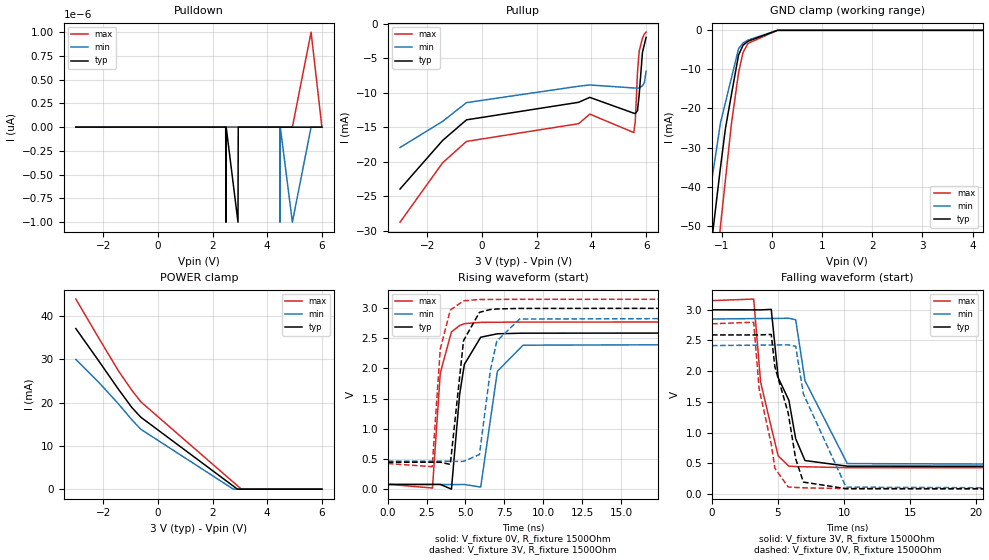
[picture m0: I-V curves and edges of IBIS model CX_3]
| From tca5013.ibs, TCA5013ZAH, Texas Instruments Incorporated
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[Model]   CX_3
Model_type   I/O
Polarity   Non-Inverting
Enable   Active-Low
Vinl = 1.2
Vinh = 1.8
Vmeas = 1.5
Vref = 3
Cref = 1pF
Rref = 1500
|   typ   min   max
C_comp   0.819p   0.538p   1.031p
|C_comp (ON state)   0.835p   0.552p   1.076p
|C_comp (OFF state)   0.819p   0.538p   1.031p
[Model spec]
|subparameter
Vinl   1.2   1.14   1.26
Vinh   1.8   1.71   1.89
[Voltage Range]   3   2.85   3.15
[Temperature Range]   27   125   -40
[Pullup Reference]   3   2.85   3.15
[Pulldown Reference]   0   0   0
[Power Clamp Reference]   3   2.85   3.15
[GND Clamp Reference]   0   0   0
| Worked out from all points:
|   GND clamp passes 1 mA (typ) near -0.12 V on its own axis
|   falling waveform, V_fixture 3V, R_fixture 1500Ohm: 20-80 % time 1.53ns typ, 2.05ns min, 1.2ns max; typ from 3 V to 0.448 V
|   rising waveform, V_fixture 0V, R_fixture 1500Ohm: 20-80 % time 634ps typ, 780ps min, 536ps max; typ from 0.08 V to 2.59 V
|   rising waveform, V_fixture 3V, R_fixture 1500Ohm: 20-80 % time 622ps typ, 770ps min, 532ps max; typ from 0.448 V to 3 V
|   falling waveform, V_fixture 0V, R_fixture 1500Ohm: 20-80 % time 1.57ns typ, 2.1ns min, 1.24ns max; typ from 2.59 V to 0.08 V
[Pulldown]
|   Voltage   I(typ)   I(min)   I(max)
-3V       0A         0A         0A
2.481V    0A         0A         0A
2.49V     -1pA       0A         0A
2.499V    0A         0A         0A
2.931V    -1pA       0A         0A
2.94V     0A         0A         0A
4.461V    0A         0A         0A
4.47V     0A         -1pA       0A
4.479V    0A         0A         0A
4.92V     0A         -1pA       0A
5.604V    0A         0A         1pA
6V        0A         0A         0A
[GND Clamp]
|   Voltage   I(typ)   I(min)   I(max)
-3V       -434mA     -224.4mA   -707.7mA
-1.38V    -74.24mA   -53.32mA   -98.3mA
-1.29V    -63.61mA   -45.71mA   -85.56mA
-1.182V   -51.54mA   -36.57mA   -70.32mA
-1.029V   -34.96mA   -23.63mA   -49.98mA
-930mV    -25.05mA   -18.42mA   -38.12mA
-813.2mV  -16.55mA   -12.27mA   -24.13mA
-669mV    -6.316mA   -4.694mA   -10.85mA
-579mV    -3.803mA   -3.238mA   -5.623mA
-480mV    -2.788mA   -2.484mA   -3.335mA
105mV     0A         0A         0A
6V        0A         0A         0A
[Pullup]
|   Voltage   I(typ)   I(min)   I(max)
-3V       -23.92mA   -17.92mA   -28.72mA
-1.443V   -16.9mA    -14.14mA   -20.13mA
-570mV    -13.92mA   -11.43mA   -17.04mA
3.534V    -11.38mA   -9.054mA   -14.47mA
3.939V    -10.67mA   -8.875mA   -13.09mA
5.55V     -12.96mA   -9.31mA    -15.76mA
5.604V    -13.01mA   -9.314mA   -14.11mA
5.685V    -12.58mA   -9.318mA   -7.007mA
5.748V    -10.22mA   -9.315mA   -3.964mA
5.866V    -4.161mA   -8.988mA   -2.102mA
5.937V    -3.011mA   -8.538mA   -1.501mA
6V        -1.993mA   -6.882mA   -1.228mA
[POWER Clamp]
|   Voltage   I(typ)   I(min)   I(max)
-3V       37.13mA    30.01mA    43.95mA
-2.172V   29.74mA    24.78mA    35.05mA
-1.443V   23.11mA    19.73mA    27.35mA
-948mV    18.85mA    16.03mA    22.83mA
-624mV    16.64mA    13.85mA    20.2mA
2.751V    749.9uA    37.34uA    1.659mA
2.904V    21.74uA    0A         826.6uA
3.048V    0A         0A         43.64uA
6V        0A         0A         0A
[Ramp]
R_load = 1500
|   typ   min   max
dV/dt_r   1.50633/6.33602e-10   1.40333/7.81109e-10   1.61297/5.3699e-10
dV/dt_f   1.53142/1.52711e-09   1.43045/2.04544e-09   1.63426/1.19826e-09
[Falling Waveform]
V_fixture = 3V
V_fixture_min = 2.85V
V_fixture_max = 3.15V
R_fixture = 1500Ohm
C_fixture = 0F
|   Time   V(typ)   V(min)   V(max)
0s        3V         2.85V      3.15V
3.163ns   2.999V     2.857V     3.175V
3.685ns   2.999V     2.858V     1.823V
4.491ns   3.007V     2.859V     1.087V
5.017ns   1.893V     2.86V      619.5mV
5.827ns   1.526V     2.862V     452.3mV
6.341ns   900.1mV    2.837V     446.7mV
7.046ns   544.4mV    1.845V     442.7mV
10.25ns   452.7mV    494.7mV    428.2mV
49.9ns    447.6mV    465.9mV    426.2mV
[Rising Waveform]
V_fixture = 0V
V_fixture_min = 0V
V_fixture_max = 0V
R_fixture = 1500Ohm
C_fixture = 0F
|   Time   V(typ)   V(min)   V(max)
0s        80.25mV    77.98mV    83.74mV
2.877ns   80.48mV    78.21mV    19.89mV
3.379ns   80.52mV    78.25mV    1.925V
4.097ns   1.257mV    78.3mV     2.606V
4.624ns   1.571V     78.34mV    2.712V
4.928ns   2.068V     78.37mV    2.743V
5.979ns   2.518V     35.79mV    2.764V
7.052ns   2.575V     1.955V     2.766V
8.704ns   2.585V     2.386V     2.769V
49.9ns    2.591V     2.417V     2.772V
[Rising Waveform]
V_fixture = 3V
V_fixture_min = 2.85V
V_fixture_max = 3.15V
R_fixture = 1500Ohm
C_fixture = 0F
|   Time   V(typ)   V(min)   V(max)
0s        447.6mV    465.8mV    426.1mV
2.859ns   447.7mV    463.4mV    373.8mV
3.379ns   447.7mV    463mV      2.323V
4.024ns   411.3mV    462.5mV    2.968V
4.874ns   2.461V     461.8mV    3.121V
5.898ns   2.93V      573.9mV    3.143V
6.595ns   2.977V     1.962V     3.144V
7.016ns   2.986V     2.455V     3.144V
8.48ns    2.995V     2.819V     3.146V
49.9ns    3V         2.85V      3.15V
[Falling Waveform]
|Gnd
V_fixture = 0V
V_fixture_min = 0V
V_fixture_max = 0V
R_fixture = 1500Ohm
C_fixture = 0F
|   Time   V(typ)   V(min)   V(max)
0s        2.591V     2.417V     2.772V
3.163ns   2.59V      2.424V     2.798V
3.569ns   2.59V      2.425V     1.719V
4.491ns   2.599V     2.427V     812mV
4.765ns   2.072V     2.427V     418.5mV
5.774ns   1.319V     2.429V     113.3mV
6.341ns   571.8mV    2.405V     105.7mV
6.926ns   193.1mV    1.628V     100.2mV
10.16ns   86.45mV    110mV      86.5mV
49.9ns    80.25mV    77.98mV    83.74mV
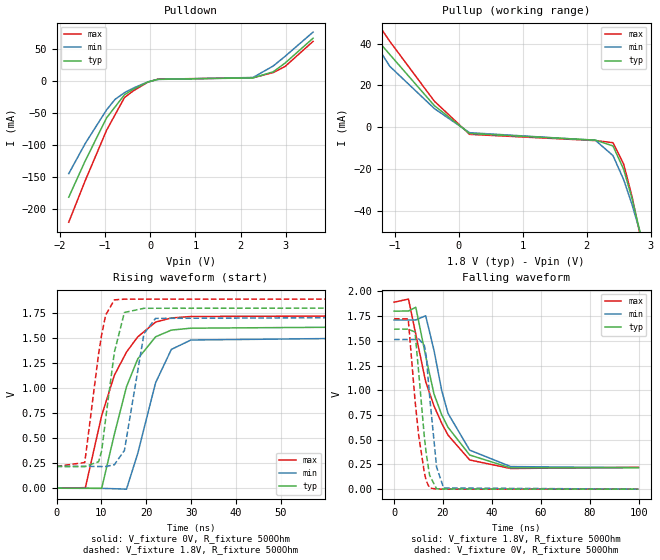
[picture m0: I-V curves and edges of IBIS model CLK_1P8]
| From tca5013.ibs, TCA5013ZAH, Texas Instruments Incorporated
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|   Model CLK
[Model]   CLK_1P8
Model_type   Output
Polarity   Non-Inverting
Vmeas = 0.9
Vref = 1.8
Cref = 1pF
Rref = 500
|   typ   min   max
C_comp   0.597p   0.445p   0.907p
|C_comp (ON state)   0.597p   0.445p   0.907p
|C_comp (OFF state)   0.592p   0.445p   0.907p
[Voltage Range]   1.8   1.71   1.89
[Temperature Range]   27   125   -40
[Pullup Reference]   1.8   1.71   1.89
[Pulldown Reference]   0   0   0
[Power Clamp Reference]   1.8   1.71   1.89
[GND Clamp Reference]   0   0   0
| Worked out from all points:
|   slope of the pulldown table from 0 to 0.27 V, typ, clamps not added: 80.3 ohm
|   slope of the pullup table from 0 to 0.27 V, typ, clamps not added: 64.9 ohm
|   falling waveform, V_fixture 1.8V, R_fixture 500Ohm: 20-80 % time 12.4ns typ, 10.7ns min, 12.9ns max; typ from 1.8 V to 0.218 V
|   rising waveform, V_fixture 0V, R_fixture 500Ohm: 20-80 % time 6.22ns typ, 5.54ns min, 7.57ns max; typ from 0 V to 1.62 V
|   rising waveform, V_fixture 1.8V, R_fixture 500Ohm: 20-80 % time 2.79ns typ, 2.97ns min, 2.98ns max; typ from 0.218 V to 1.8 V
|   falling waveform, V_fixture 0V, R_fixture 500Ohm: 20-80 % time 3.62ns typ, 3.34ns min, 4.13ns max; typ from 1.62 V to 0 V
[Pulldown]
|   Voltage   I(typ)   I(min)   I(max)
-1.8V     -181.5mA   -144.7mA   -220.6mA
-1.438V   -125mA     -97.81mA   -156mA
-963mV    -57.33mA   -44.83mA   -76.73mA
-774mV    -40.13mA   -28.44mA   -52.34mA
-567.1mV  -21.31mA   -18.07mA   -25.64mA
-379.8mV  -12.97mA   -11.16mA   -15.54mA
-50.4mV   -1.481mA   -1.108mA   -1.576mA
171mV     2.826mA    2.586mA    3.048mA
2.272V    4.956mA    5.651mA    5.216mA
2.72V     14.57mA    23.66mA    13.38mA
2.979V    28.07mA    38.59mA    22.75mA
3.6V      67.05mA    76.62mA    62.13mA
[Pullup]
|   Voltage   I(typ)   I(min)   I(max)
-1.8V     65mA       67.66mA    73.64mA
-1.438V   47.62mA    46.48mA    57.36mA
-1.075V   34.73mA    29.08mA    41.03mA
-379.8mV  10.31mA    8.9mA      12.43mA
171mV     -3.048mA   -2.661mA   -3.448mA
2.137V    -6.212mA   -6.303mA   -6.432mA
2.412V    -9.003mA   -13.62mA   -7.448mA
2.579V    -20.22mA   -25.14mA   -17.73mA
2.709V    -34.17mA   -37.01mA   -33.2mA
2.866V    -54.2mA    -53.43mA   -56.12mA
3.06V     -81.74mA   -75.9mA    -87.8mA
3.6V      -165.3mA   -145.3mA   -183mA
[Ramp]
R_load = 500
|   typ   min   max
dV/dt_r   0.972083/6.21813e-09   0.908449/5.5359e-09   1.03477/7.56584e-09
dV/dt_f   0.949299/1.23787e-08   0.895838/1.06834e-08   1.00117/1.29267e-08
[Falling Waveform]
V_fixture = 1.8V
V_fixture_min = 1.71V
V_fixture_max = 1.89V
R_fixture = 500Ohm
C_fixture = 0F
|   Time   V(typ)   V(min)   V(max)
0s        1.8V       1.71V      1.89V
5.898ns   1.801V     1.711V     1.922V
8.884ns   1.839V     1.711V     1.566V
12.93ns   1.345V     1.753V     1.086V
16.32ns   963.2mV    1.404V     841.6mV
19.49ns   750.9mV    997.5mV    665.9mV
22.05ns   626.1mV    766.7mV    547.1mV
30.92ns   345.3mV    394.8mV    295.2mV
47.71ns   214.8mV    228.4mV    208.9mV
99.9ns    217.8mV    216.9mV    221.4mV
[Rising Waveform]
V_fixture = 0V
V_fixture_min = 0V
V_fixture_max = 0V
R_fixture = 500Ohm
C_fixture = 0F
|   Time   V(typ)   V(min)   V(max)
0s        72.81nV    528.5nV    56.66nV
6.428ns   -1.095mV   40.67uV    5.639mV
10.06ns   -846.4uV   -1.522mV   726.4mV
12.88ns   538.1mV    -5.119mV   1.128V
15.59ns   1.014V     -9.441mV   1.361V
18.09ns   1.292V     347.5mV    1.512V
22.07ns   1.513V     1.054V     1.66V
25.58ns   1.58V      1.387V     1.701V
29.94ns   1.599V     1.481V     1.716V
99.9ns    1.62V      1.514V     1.725V
[Rising Waveform]
V_fixture = 1.8V
V_fixture_min = 1.71V
V_fixture_max = 1.89V
R_fixture = 500Ohm
C_fixture = 0F
|   Time   V(typ)   V(min)   V(max)
0s        217.5mV    218.2mV    217.9mV
6.289ns   216.4mV    218.3mV    256.9mV
9.385ns   265mV      217.1mV    1.348V
10.06ns   374mV      216.3mV    1.534V
10.95ns   695.6mV    217.3mV    1.73V
12.88ns   1.358V     234.6mV    1.882V
15.12ns   1.756V     376.8mV    1.889V
19.49ns   1.798V     1.545V     1.889V
22.05ns   1.798V     1.697V     1.889V
99.9ns    1.8V       1.71V      1.89V
[Falling Waveform]
|Gnd
V_fixture = 0V
V_fixture_min = 0V
V_fixture_max = 0V
R_fixture = 500Ohm
C_fixture = 0F
|   Time   V(typ)   V(min)   V(max)
0s        1.618V     1.513V     1.723V
5.787ns   1.618V     1.513V     1.722V
8.573ns   1.589V     1.513V     896.8mV
10.08ns   1.18V      1.52V      541.8mV
12.4ns    523.8mV    1.452V     164.9mV
13.19ns   355.5mV    1.335V     81.77mV
14.54ns   139.8mV    940.3mV    12.54mV
17.39ns   3.621mV    223.5mV    560uV
20.25ns   1.613mV    12.29mV    843.7uV
99.9ns    102.4uV    166.3uV    64.26uV
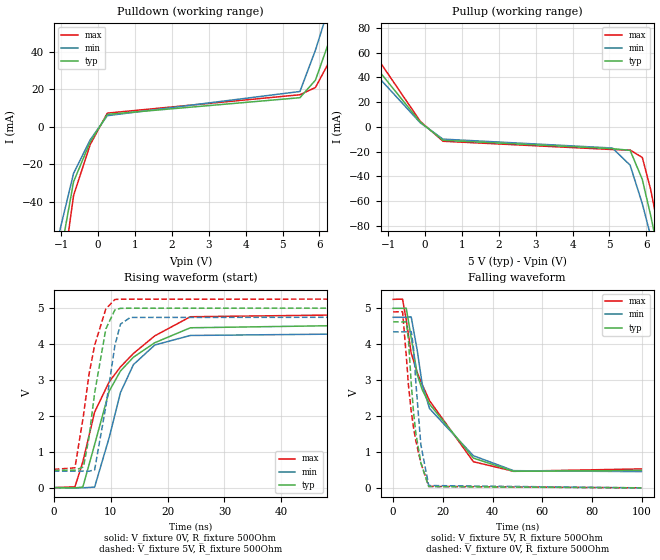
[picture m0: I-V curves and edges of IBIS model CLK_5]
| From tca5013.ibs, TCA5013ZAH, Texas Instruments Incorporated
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[Model]   CLK_5
Model_type   Output
Polarity   Non-Inverting
Vmeas = 2.5
Vref = 5
Cref = 1pF
Rref = 500
|   typ   min   max
C_comp   0.937p   0.723p   1.081p
|C_comp (ON state)   0.950p   0.730p   1.090p
|C_comp (OFF state)   0.937p   0.723p   1.081p
[Voltage Range]   5   4.75   5.25
[Temperature Range]   27   125   -40
[Pullup Reference]   5   4.75   5.25
[Pulldown Reference]   0   0   0
[Power Clamp Reference]   5   4.75   5.25
[GND Clamp Reference]   0   0   0
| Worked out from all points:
|   slope of the pulldown table from 0 to 0.75 V, typ, clamps not added: 77.3 ohm
|   slope of the pullup table from 0 to 0.75 V, typ, clamps not added: 60.3 ohm
|   falling waveform, V_fixture 5V, R_fixture 500Ohm: 20-80 % time 16.5ns typ, 15.2ns min, 16.2ns max; typ from 5 V to 0.485 V
|   rising waveform, V_fixture 0V, R_fixture 500Ohm: 20-80 % time 7.69ns typ, 5.2ns min, 9.94ns max; typ from 0 V to 4.63 V
|   rising waveform, V_fixture 5V, R_fixture 500Ohm: 20-80 % time 2.5ns typ, 2.42ns min, 2.91ns max; typ from 0.486 V to 5 V
|   falling waveform, V_fixture 0V, R_fixture 500Ohm: 20-80 % time 3.91ns typ, 3.1ns min, 5.07ns max; typ from 4.62 V to 0 V
[Pulldown]
|   Voltage   I(typ)   I(min)   I(max)
-5V       -2.371A    -1.943A    -2.674A
-2.495V   -297.4mA   -245.6mA   -349.6mA
-1.25V    -100.1mA   -78.8mA    -127.6mA
-1.04V    -70.39mA   -55.45mA   -90.18mA
-665mV    -29.23mA   -24.77mA   -36.56mA
-215mV    -8.057mA   -6.927mA   -9.442mA
250mV     6.693mA    6.01mA     7.374mA
5.47V     15.6mA     18.91mA    17.18mA
5.89V     24.96mA    40.96mA    21.05mA
6.28V     46.74mA    65.38mA    35.36mA
7.675V    147.7mA    163.9mA    140.1mA
10V       342.3mA    375.7mA    355.4mA
[Pullup]
|   Voltage   I(typ)   I(min)   I(max)
-5V       273.3mA    294.8mA    295.7mA
-2.3V     96.77mA    99.19mA    104.5mA
-1.25V    45.3mA     39.76mA    53.7mA
-125mV    3.799mA    3.278mA    4.46mA
490mV     -10.77mA   -9.84mA    -11.56mA
5.08V     -17.53mA   -17.02mA   -18.24mA
5.56V     -18.91mA   -30.91mA   -18.7mA
5.89V     -42.38mA   -61.97mA   -24.65mA
6.115V    -71.26mA   -87.96mA   -50.3mA
6.25V     -90.54mA   -104.6mA   -70.56mA
7.735V    -327.5mA   -309.1mA   -334.5mA
10V       -2.371A    -2.188A    -2.426A
[Ramp]
R_load = 500
|   typ   min   max
dV/dt_r   2.7772/7.68381e-09   2.61104/5.20304e-09   2.94322/9.89574e-09
dV/dt_f   2.70922/1.65153e-08   2.57881/1.52113e-08   2.83329/1.62101e-08
[Falling Waveform]
V_fixture = 5V
V_fixture_min = 4.75V
V_fixture_max = 5.25V
R_fixture = 500Ohm
C_fixture = 0F
|   Time   V(typ)   V(min)   V(max)
0s        5V         4.75V      5.25V
3.789ns   5V         4.75V      5.256V
5.269ns   5.005V     4.75V      4.681V
7.273ns   4.195V     4.762V     3.753V
9.731ns   3.145V     3.818V     3.21V
11.72ns   2.732V     2.881V     2.873V
14.68ns   2.329V     2.207V     2.425V
32.3ns    829.2mV    895.1mV    728.3mV
48.5ns    461.1mV    478.7mV    461.3mV
99.9ns    484.6mV    452mV      527.9mV
[Rising Waveform]
V_fixture = 0V
V_fixture_min = 0V
V_fixture_max = 0V
R_fixture = 500Ohm
C_fixture = 0F
|   Time   V(typ)   V(min)   V(max)
0s        112.9nV    473.4nV    94.34nV
3.714ns   -6.194mV   -4.421mV   23.1mV
5.099ns   14.87mV    -6.07mV    717.7mV
7.175ns   1.2V       15.94mV    2.104V
9.731ns   2.687V     1.391V     2.946V
11.72ns   3.248V     2.648V     3.362V
14ns      3.633V     3.426V     3.737V
17.75ns   4.036V     3.972V     4.227V
24.01ns   4.452V     4.238V     4.759V
99.9ns    4.629V     4.352V     4.905V
[Rising Waveform]
V_fixture = 5V
V_fixture_min = 4.75V
V_fixture_max = 5.25V
R_fixture = 500Ohm
C_fixture = 0F
|   Time   V(typ)   V(min)   V(max)
0s        486mV      461mV      509.1mV
3.714ns   486.2mV    461.2mV    551.4mV
5.207ns   574.4mV    461.3mV    2.006V
6.174ns   1.388V     456.8mV    3.142V
7.175ns   2.631V     496.9mV    3.965V
9.149ns   4.42V      2.262V     4.98V
10.74ns   4.95V      3.959V     5.24V
11.72ns   4.994V     4.553V     5.249V
13.45ns   4.997V     4.74V      5.249V
99.9ns    5V         4.75V      5.25V
[Falling Waveform]
|Gnd
V_fixture = 0V
V_fixture_min = 0V
V_fixture_max = 0V
R_fixture = 500Ohm
C_fixture = 0F
|   Time   V(typ)   V(min)   V(max)
0s        4.622V     4.345V     4.899V
3.81ns    4.622V     4.345V     4.907V
5.306ns   4.621V     4.345V     3.667V
6.174ns   4.12V      4.345V     2.859V
7.311ns   2.891V     4.353V     2.118V
8.241ns   2.092V     3.874V     1.668V
9.149ns   1.522V     2.937V     1.31V
11.16ns   693.5mV    1.203V     697.9mV
14.34ns   35.44mV    64.72mV    40.68mV
99.9ns    33.66uV    72.92uV    10.41uV
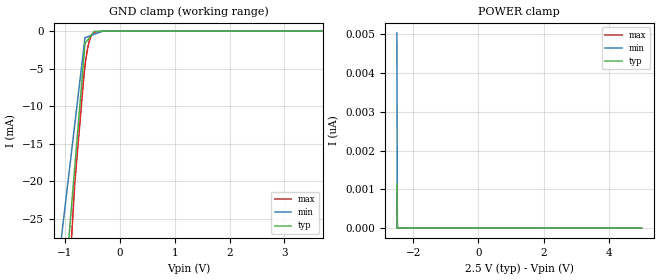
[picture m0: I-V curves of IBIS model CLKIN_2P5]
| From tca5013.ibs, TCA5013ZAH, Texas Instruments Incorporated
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[Model]   CLKIN_2P5
Model_type   Input
Vinl = .5
Vinh = 2.0
|   typ   min   max
C_comp   0.731p   0.503p   0.930p
[Model spec]
|subparameter
Vinl   0.5   0.45   0.55
Vinh   2.0   1.8   2.2
[Voltage Range]   2.5   2.25   2.75
[Temperature Range]   27   125   -40
[Power Clamp Reference]   2.5   2.25   2.75
[GND Clamp Reference]   0   0   0
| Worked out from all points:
|   GND clamp passes 1 mA (typ) near -0.57 V on its own axis
[GND Clamp]
|   Voltage   I(typ)   I(min)   I(max)
-2.5V     -203.5mA   -158.5mA   -265.9mA
-1.383V   -68.06mA   -47.4mA    -91.06mA
-820mV    -18.25mA   -12.51mA   -20.38mA
-647.5mV  -2.977mA   -1.809mA   -5.543mA
-632.5mV  -1.649mA   -878.3uA   -4.63mA
-610mV    -1.431mA   -817.7uA   -3.421mA
-587.5mV  -1.212mA   -757.1uA   -2.416mA
-557.5mV  -921.6uA   -676.2uA   -1.405mA
-520mV    -557.9uA   -575.1uA   -626.6uA
-467.5mV  -48.79uA   -433.7uA   -163.3uA
-307mV    -424.6nA   -1.005uA   -651.4nA
5V        0A         0A         0A
[POWER Clamp]
|   Voltage   I(typ)   I(min)   I(max)
-2.5V     1.151nA    5.033nA    768pA
-2.485V   0A         0A         0A
-512.5mV  0A         0A         0A
5V        0A         0A         0A
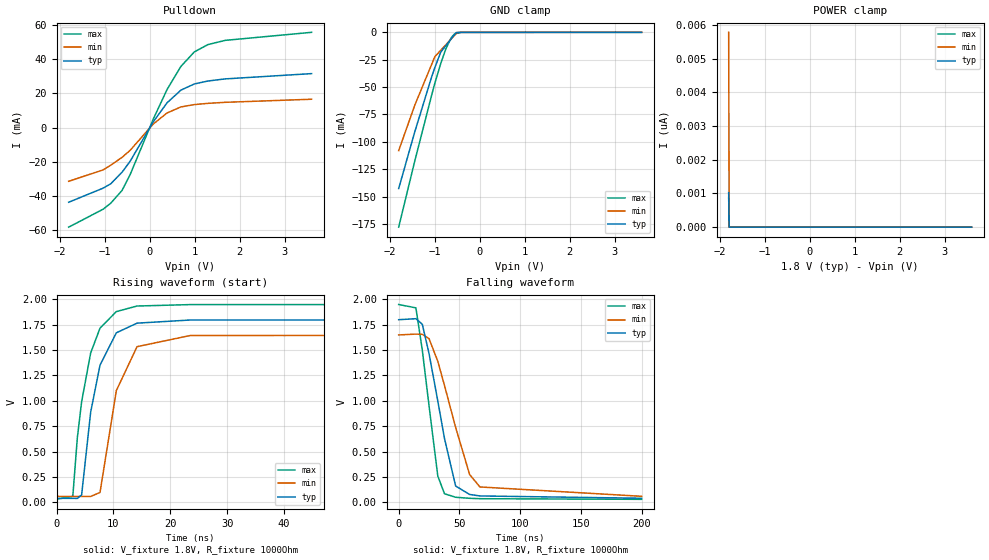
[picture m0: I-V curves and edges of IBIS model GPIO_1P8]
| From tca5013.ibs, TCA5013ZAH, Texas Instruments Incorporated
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|   Model GPIO
[Model]   GPIO_1P8
Model_type   I/O_open_drain
Polarity   Non-Inverting
Enable   Active-Low
Vinl = .4
Vinh = 1.4
Vmeas = 0.9
Vref = 1.8
Cref = 15pF
Rref = 1000
|   typ   min   max
C_comp   0.924p   0.657p   1.281p
|C_comp (Low state)   1.051p   0.694p   1.583p
|C_comp (High state)   0.924p   0.657p   1.281p
[Voltage Range]   1.8   1.65   1.95
[Temperature Range]   27   125   -40
[Pullup Reference]   1.8   1.65   1.95
[Pulldown Reference]   0   0   0
[Power Clamp Reference]   1.8   1.65   1.95
[GND Clamp Reference]   0   0   0
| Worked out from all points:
|   slope of the pulldown table from 0 to 0.27 V, typ, clamps not added: 25.3 ohm
|   GND clamp passes 1 mA (typ) near -0.54 V on its own axis
|   falling waveform, V_fixture 1.8V, R_fixture 1000Ohm: 20-80 % time 16ns typ, 21.8ns min, 11.7ns max; typ from 1.8 V to 0.039 V
|   rising waveform, V_fixture 1.8V, R_fixture 1000Ohm: 20-80 % time 3.18ns typ, 3.28ns min, 3.15ns max; typ from 0.039 V to 1.8 V
[Pulldown]
|   Voltage   I(typ)   I(min)   I(max)
-1.8V     -43.54mA   -31.32mA   -58.1mA
-1.035V   -35.32mA   -24.65mA   -47.62mA
-865.8mV  -32.8mA    -21.91mA   -44.14mA
-612mV    -25.96mA   -17.3mA    -36.59mA
-433.8mV  -19.6mA    -13.22mA   -27.4mA
79.2mV    3.391mA    2.126mA    4.96mA
387mV     14.54mA    8.61mA     22.29mA
694.8mV   21.94mA    12.13mA    35.81mA
991.8mV   25.54mA    13.5mA     44.26mA
1.294V    27.27mA    14.23mA    48.54mA
1.678V    28.51mA    14.83mA    51.02mA
3.6V      31.6mA     16.63mA    55.72mA
[GND Clamp]
|   Voltage   I(typ)   I(min)   I(max)
-1.8V     -142.7mA   -108.1mA   -178mA
-1.438V   -90.37mA   -66.14mA   -116.9mA
-1.065V   -40.44mA   -29.09mA   -57.11mA
-995.4mV  -32.15mA   -22.18mA   -46.43mA
-865.8mV  -18.17mA   -16.42mA   -28.63mA
-752.4mV  -12.25mA   -11.39mA   -15.16mA
-633.6mV  -6.051mA   -6.115mA   -4.986mA
-563.4mV  -2.387mA   -2.998mA   -1.65mA
-522.2mV  -237.1uA   -1.169mA   -1.146mA
-500.7mV  -181.3uA   -214.9uA   -883.2uA
-412.2mV  -15.04uA   -35.46uA   -52.22uA
3.6V      0A         0A         0A
[POWER Clamp]
|   Voltage   I(typ)   I(min)   I(max)
-1.8V     1.028nA    5.783nA    879.5pA
-1.789V   0A         0A         0A
-1.784V   0A         0A         0A
3.6V      0A         0A         0A
[Ramp]
R_load = 1000
|   typ   min   max
dV/dt_r   1.05672/3.17753e-09   0.955735/3.275e-09   1.15295/3.14952e-09
dV/dt_f   1.05653/1.59691e-08   0.954968/2.17298e-08   1.15291/1.16492e-08
[Falling Waveform]
V_fixture = 1.8V
V_fixture_min = 1.65V
V_fixture_max = 1.95V
R_fixture = 1000Ohm
C_fixture = 0F
|   Time   V(typ)   V(min)   V(max)
0s        1.8V       1.65V      1.95V
14.16ns   1.81V      1.658V     1.917V
19.45ns   1.755V     1.656V     1.5V
25ns      1.465V     1.613V     949.5mV
32.21ns   997.5mV    1.389V     257.5mV
37.71ns   628.1mV    1.151V     83.44mV
46.88ns   159.5mV    737.6mV    48.98mV
58.39ns   76.61mV    272.8mV    38.63mV
66.88ns   61.77mV    150.5mV    34.68mV
199.9ns   39.11mV    58.38mV    28.48mV
[Rising Waveform]
V_fixture = 1.8V
V_fixture_min = 1.65V
V_fixture_max = 1.95V
R_fixture = 1000Ohm
C_fixture = 0F
|   Time   V(typ)   V(min)   V(max)
0s        38.81mV    57.11mV    28.42mV
2.864ns   37.8mV     56.89mV    58.21mV
3.657ns   37.52mV    56.83mV    633.5mV
4.412ns   70.71mV    56.77mV    989.9mV
6.004ns   888.2mV    56.65mV    1.472V
7.65ns    1.352V     96.16mV    1.717V
10.52ns   1.671V     1.101V     1.88V
14.16ns   1.766V     1.534V     1.935V
23.5ns    1.797V     1.644V     1.949V
199.9ns   1.8V       1.65V      1.95V
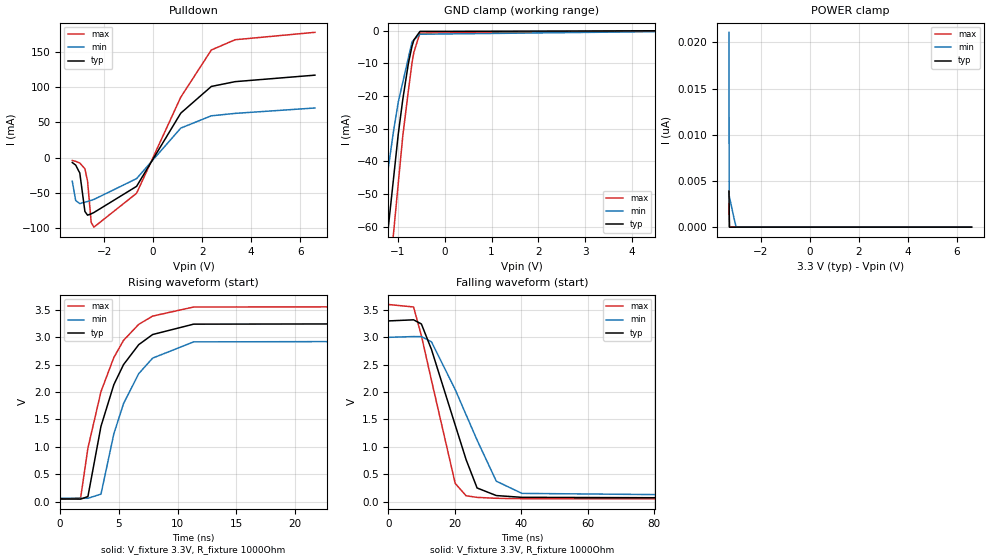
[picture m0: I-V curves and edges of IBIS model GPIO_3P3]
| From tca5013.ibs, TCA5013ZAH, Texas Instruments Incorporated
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[Model]   GPIO_3P3
Model_type   I/O_open_drain
Polarity   Non-Inverting
Enable   Active-Low
Vinl = .4
Vinh = 1.4
Vmeas = 1.65
Vref = 3.3
Cref = 15pF
Rref = 1000
|   typ   min   max
C_comp   1.169p   0.816p   1.405p
|C_comp (Low state)   1.505p   1.001p   1.852p
|C_comp (High state)   1.169p   0.816p   1.405p
[Voltage Range]   3.3   3   3.6
[Temperature Range]   27   125   -40
[Pullup Reference]   3.3   3   3.6
[Pulldown Reference]   0   0   0
[Power Clamp Reference]   3.3   3   3.6
[GND Clamp Reference]   0   0   0
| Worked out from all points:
|   slope of the pulldown table from 0 to 0.495 V, typ, clamps not added: 16.4 ohm
|   GND clamp passes 1 mA (typ) near -0.59 V on its own axis
|   falling waveform, V_fixture 3.3V, R_fixture 1000Ohm: 20-80 % time 10.1ns typ, 12.7ns min, 7.98ns max; typ from 3.3 V to 0.048 V
|   rising waveform, V_fixture 3.3V, R_fixture 1000Ohm: 20-80 % time 3.03ns typ, 3.04ns min, 3.05ns max; typ from 0.048 V to 3.3 V
[Pulldown]
|   Voltage   I(typ)   I(min)   I(max)
-3.3V     -6.862mA   -33.24mA   -3.999mA
-3.161V   -10.47mA   -60.76mA   -5.135mA
-2.993V   -21.77mA   -65.01mA   -7.509mA
-2.785V   -76.24mA   -63.04mA   -15.74mA
-2.676V   -81.46mA   -61.99mA   -33.44mA
-2.528V   -79.48mA   -60.35mA   -91.76mA
-2.419V   -77.7mA    -59.15mA   -98.41mA
-676.5mV  -40.54mA   -29.62mA   -50.38mA
1.125V    63.12mA    41.97mA    85.74mA
2.373V    101mA      59.37mA    152.7mA
3.343V    107.8mA    62.82mA    167.2mA
6.6V      117mA      70.48mA    177.7mA
[GND Clamp]
|   Voltage   I(typ)   I(min)   I(max)
-3.3V     -712.5mA   -354.1mA   -998.9mA
-1.478V   -96.93mA   -71.4mA    -123.6mA
-1.379V   -83.67mA   -59.71mA   -107.3mA
-1.221V   -62.46mA   -43.72mA   -81.3mA
-1.092V   -45.22mA   -30.73mA   -61.95mA
-990.7mV  -31.6mA    -21.84mA   -46.68mA
-894.3mV  -21.05mA   -15.8mA    -32.19mA
-775.5mV  -10.07mA   -8.363mA   -18.44mA
-696.3mV  -4.718mA   -3.403mA   -9.759mA
-656.7mV  -2.856mA   -2.871mA   -6.565mA
-528mV    -269.9uA   -1.141mA   -787.1uA
6.6V      0A         0A         0A
[POWER Clamp]
|   Voltage   I(typ)   I(min)   I(max)
-3.3V     3.895nA    21.09nA    2.502nA
-3.29V    1.948nA    3.412nA    1.251nA
-3.28V    0A         3.276nA    0A
-3.102V   0A         1.066nA    0A
-3.013V   0A         80.95pA    0A
-2.993V   0A         0A         0A
6.6V      0A         0A         0A
[Ramp]
R_load = 1000
|   typ   min   max
dV/dt_r   1.95138/3.01966e-09   1.76354/3.02464e-09   2.13616/3.04375e-09
dV/dt_f   1.95131/1.01082e-08   1.7633/1.27083e-08   2.13615/7.97282e-09
[Falling Waveform]
V_fixture = 3.3V
V_fixture_min = 3V
V_fixture_max = 3.6V
R_fixture = 1000Ohm
C_fixture = 0F
|   Time   V(typ)   V(min)   V(max)
0s        3.3V       3V         3.6V
7.553ns   3.32V      3.014V     3.555V
9.916ns   3.244V     3.013V     3.03V
12.95ns   2.779V     2.918V     2.215V
20.11ns   1.396V     2.045V     329.6mV
23.4ns    763.5mV    1.583V     104.6mV
26.7ns    247.2mV    1.122V     75.48mV
32.49ns   108.7mV    371.5mV    58.29mV
40.22ns   76.12mV    148.3mV    51.47mV
199.9ns   47.81mV    61.16mV    39.75mV
[Rising Waveform]
V_fixture = 3.3V
V_fixture_min = 3V
V_fixture_max = 3.6V
R_fixture = 1000Ohm
C_fixture = 0F
|   Time   V(typ)   V(min)   V(max)
0s        47.7mV     60.76mV    39.73mV
1.744ns   43.49mV    59.12mV    64.29mV
2.366ns   90.61mV    58.54mV    977.5mV
3.479ns   1.375V     135.2mV    2.009V
4.573ns   2.135V     1.236V     2.631V
5.4ns     2.502V     1.789V     2.945V
6.692ns   2.866V     2.336V     3.237V
7.876ns   3.051V     2.62V      3.388V
11.37ns   3.241V     2.917V     3.554V
199.9ns   3.3V       3V         3.6V
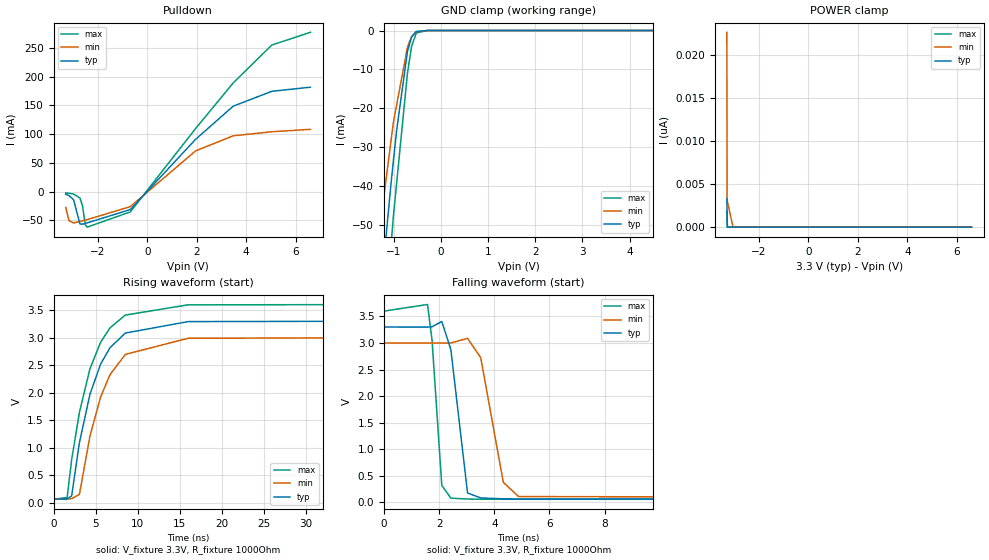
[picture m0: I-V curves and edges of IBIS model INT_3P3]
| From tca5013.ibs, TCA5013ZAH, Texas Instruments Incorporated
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[Model]   INT_3P3
Model_type   Open_drain
Polarity   Non-Inverting
Vmeas = 1.65
Vref = 3.3
Cref = 15pF
Rref = 1000
|   typ   min   max
C_comp   2.166p   1.754p   2.419p
|C_comp (Low state)   2.166p   1.754p   2.419p
|C_comp (High state)   2.217p   1.811p   2.443p
[Voltage Range]   3.3   3   3.6
[Temperature Range]   27   125   -40
[Pullup Reference]   3.3   3   3.6
[Pulldown Reference]   0   0   0
[Power Clamp Reference]   3.3   3   3.6
[GND Clamp Reference]   0   0   0
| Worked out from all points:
|   slope of the pulldown table from 0 to 0.495 V, typ, clamps not added: 20.7 ohm
|   GND clamp passes 1 mA (typ) near -0.59 V on its own axis
|   falling waveform, V_fixture 3.3V, R_fixture 1000Ohm: 20-80 % time 379ps typ, 577ps min, 259ps max; typ from 3.3 V to 0.063 V
|   rising waveform, V_fixture 3.3V, R_fixture 1000Ohm: 20-80 % time 3.38ns typ, 3.43ns min, 3.38ns max; typ from 0.063 V to 3.3 V
[Pulldown]
|   Voltage   I(typ)   I(min)   I(max)
-3.3V     -4.555mA   -27.73mA   -2.364mA
-3.171V   -6.866mA   -50.3mA    -2.892mA
-2.983V   -14.21mA   -54.59mA   -4.271mA
-2.726V   -56.32mA   -51.9mA    -11.28mA
-2.627V   -56.58mA   -50.84mA   -23.86mA
-2.508V   -55.26mA   -49.52mA   -57.48mA
-2.434V   -54.44mA   -48.69mA   -61.84mA
-686.4mV  -31.19mA   -26.18mA   -35.24mA
1.947V    90.67mA    70.63mA    109.3mA
3.472V    148.5mA    96.98mA    188.8mA
5.036V    174.4mA    104.1mA    254.9mA
6.6V      181.6mA    108.3mA    277mA
[GND Clamp]
|   Voltage   I(typ)   I(min)   I(max)
-3.3V     -712.4mA   -354.8mA   -998.7mA
-1.3V     -71.46mA   -52.43mA   -93.79mA
-1.28V    -68.69mA   -50.37mA   -90.63mA
-1.241V   -63.6mA    -46.25mA   -84.29mA
-1.053V   -39.41mA   -28.36mA   -55.41mA
-1.003V   -33.52mA   -23.65mA   -47.81mA
-933.9mV  -25.69mA   -19.16mA   -39.26mA
-705mV    -5.415mA   -4.3mA     -11mA
-617.1mV  -1.645mA   -1.56mA    -4.064mA
-518.1mV  -231.4uA   -354.8uA   -634.7uA
-290.4mV  -428.4nA   -2.998uA   -329.7nA
6.6V      0A         0A         0A
[POWER Clamp]
|   Voltage   I(typ)   I(min)   I(max)
-3.3V     3.297nA    22.69nA    1.85nA
-3.29V    1.649nA    3.161nA    925pA
-3.28V    0A         3.02nA     0A
-3.092V   0A         538.6pA    0A
-3.053V   0A         61.28pA    0A
-3.033V   0A         0A         0A
6.6V      0A         0A         0A
[Ramp]
R_load = 1000
|   typ   min   max
dV/dt_r   1.94209/3.38126e-09   1.75891/3.4336e-09   2.12478/3.37692e-09
dV/dt_f   1.94209/3.79437e-10   1.75895/5.77471e-10   2.12477/2.59448e-10
[Falling Waveform]
V_fixture = 3.3V
V_fixture_min = 3V
V_fixture_max = 3.6V
R_fixture = 1000Ohm
C_fixture = 0F
|   Time   V(typ)   V(min)   V(max)
0s        3.3V       3V         3.6V
1.577ns   3.298V     2.999V     3.724V
1.742ns   3.306V     2.999V     3.044V
2.094ns   3.405V     2.998V     321mV
2.423ns   2.876V     3V         80.75mV
3.028ns   178.6mV    3.087V     64.37mV
3.507ns   84.51mV    2.723V     60.76mV
4.326ns   68.28mV    377.2mV    59.51mV
4.882ns   65.49mV    110.9mV    59.28mV
49.9ns    63.18mV    68.41mV    58.71mV
[Rising Waveform]
V_fixture = 3.3V
V_fixture_min = 3V
V_fixture_max = 3.6V
R_fixture = 1000Ohm
C_fixture = 0F
|   Time   V(typ)   V(min)   V(max)
0s        63.18mV    68.41mV    58.71mV
1.619ns   64.26mV    64.48mV    93.65mV
2.155ns   122.3mV    71.59mV    781.5mV
3.076ns   1.089V     147.9mV    1.639V
4.326ns   1.967V     1.207V     2.431V
5.591ns   2.516V     1.917V     2.912V
6.702ns   2.813V     2.322V     3.174V
8.534ns   3.081V     2.693V     3.408V
15.99ns   3.289V     2.986V     3.594V
49.9ns    3.3V       3V         3.6V
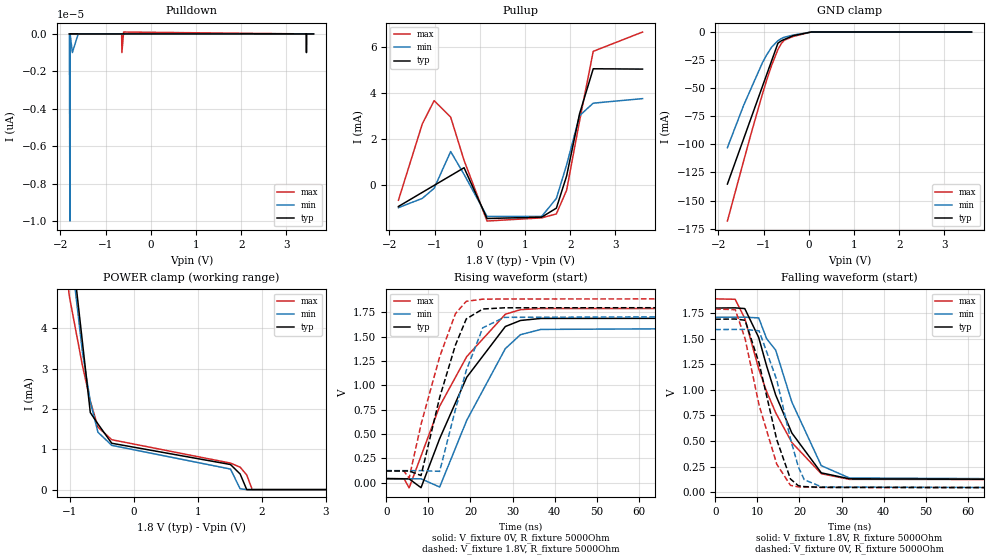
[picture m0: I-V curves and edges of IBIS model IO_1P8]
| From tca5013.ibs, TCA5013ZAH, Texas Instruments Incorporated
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|   Model IO
[Model]   IO_1P8
Model_type   I/O
Polarity   Non-Inverting
Enable   Active-Low
Vinl = .72
Vinh = 1.08
Vmeas = 0.9
Vref = 1.8
Cref = 1pF
Rref = 5000
|   typ   min   max
C_comp   0.597p   0.445p   0.907p
|C_comp (ON state)   0.597p   0.445p   0.907p
|C_comp (OFF state)   0.592p   0.445p   0.907p
[Model spec]
|subparameter
Vinl   0.72   0.684   0.756
Vinh   1.08   1.026   1.134
[Voltage Range]   1.8   1.71   1.89
[Temperature Range]   27   125   -40
[Pullup Reference]   1.8   1.71   1.89
[Pulldown Reference]   0   0   0
[Power Clamp Reference]   1.8   1.71   1.89
[GND Clamp Reference]   0   0   0
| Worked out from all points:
|   slope of the pullup table from 0 to 0.27 V, typ, clamps not added: 527 ohm
|   GND clamp passes 1 mA (typ) near -0.10 V on its own axis
|   falling waveform, V_fixture 1.8V, R_fixture 5000Ohm: 20-80 % time 9.09ns typ, 8.22ns min, 10.2ns max; typ from 1.8 V to 0.122 V
|   rising waveform, V_fixture 0V, R_fixture 5000Ohm: 20-80 % time 11.1ns typ, 10.1ns min, 12.3ns max; typ from 0.043 V to 1.69 V
|   rising waveform, V_fixture 1.8V, R_fixture 5000Ohm: 20-80 % time 6.47ns typ, 6.11ns min, 6.94ns max; typ from 0.122 V to 1.8 V
|   falling waveform, V_fixture 0V, R_fixture 5000Ohm: 20-80 % time 5.69ns typ, 6.04ns min, 6.22ns max; typ from 1.69 V to 0.043 V
[Pulldown]
|   Voltage   I(typ)   I(min)   I(max)
-1.8V     0A         0A         0A
-1.789V   0A         -10pA      0A
-1.784V   0A         0A         0A
-1.735V   0A         -1pA       0A
-1.606V   0A         0A         0A
-644.4mV  0A         0A         0A
-639mV    0A         0A         -1pA
-601.2mV  0A         0A         100fA
3.438V    0A         0A         0A
3.443V    -1pA       0A         0A
3.449V    0A         0A         0A
3.6V      0A         0A         0A
[GND Clamp]
|   Voltage   I(typ)   I(min)   I(max)
-1.8V     -135.3mA   -102.9mA   -168.2mA
-1.438V   -94.7mA    -64.94mA   -114.3mA
-1.271V   -75.93mA   -49.7mA    -89.73mA
-1.025V   -48.33mA   -27.31mA   -55.18mA
-936mV    -38.38mA   -20.67mA   -43.39mA
-821.3mV  -25.51mA   -13.39mA   -29.59mA
-682.2mV  -9.917mA   -7.743mA   -15.53mA
-601.2mV  -7.629mA   -5.624mA   -9.831mA
-541.8mV  -6.608mA   -4.639mA   -7.271mA
-347.4mV  -3.267mA   -2.721mA   -3.958mA
52.2mV    0A         0A         0A
3.6V      0A         0A         0A
[Pullup]
|   Voltage   I(typ)   I(min)   I(max)
-1.8V     -952.7uA   -1.004mA   -682.5uA
-1.271V   -337.6uA   -599.3uA   2.645mA
-1.01V    -34.04uA   -161.5uA   3.657mA
-644.4mV  390.4uA    1.44mA     2.941mA
-347.4mV  735.6uA    444uA      1.054mA
160.2mV   -1.476mA   -1.385mA   -1.585mA
1.37V     -1.416mA   -1.382mA   -1.448mA
1.694V    -1.024mA   -600.2uA   -1.276mA
1.921V    379.4uA    862.8uA    -239.5uA
2.207V    3.085mA    3.003mA    2.772mA
2.509V    5.045mA    3.547mA    5.804mA
3.6V      5.031mA    3.745mA    6.645mA
[POWER Clamp]
|   Voltage   I(typ)   I(min)   I(max)
-1.8V     17.78mA    18.81mA    18.22mA
-1.271V   10.27mA    10.29mA    8.489mA
-1.01V    6.559mA    6.234mA    4.797mA
-806.4mV  3.674mA    3.425mA    3.085mA
-682.2mV  1.911mA    2.183mA    2.199mA
-563.4mV  1.631mA    1.425mA    1.551mA
-347.4mV  1.15mA     1.098mA    1.238mA
1.51V     622.6uA    509.6uA    657.4uA
1.661V    387.3uA    19.99uA    556.7uA
1.764V    0A         0A         364.1uA
1.85V     0A         0A         0A
3.6V      0A         0A         0A
[Ramp]
R_load = 5000
|   typ   min   max
dV/dt_r   0.989086/1.10693e-08   0.928638/1.00678e-08   1.04797/1.22586e-08
dV/dt_f   1.00653/9.05178e-09   0.950591/8.1991e-09   1.0601/1.0241e-08
[Falling Waveform]
V_fixture = 1.8V
V_fixture_min = 1.71V
V_fixture_max = 1.89V
R_fixture = 5000Ohm
C_fixture = 0F
|   Time   V(typ)   V(min)   V(max)
0s        1.8V       1.71V      1.89V
4.734ns   1.802V     1.711V     1.886V
7.018ns   1.795V     1.711V     1.7V
10.32ns   1.513V     1.704V     1.207V
12.19ns   1.236V     1.502V     985.1mV
14.36ns   949.5mV    1.388V     776.7mV
18.2ns    578.3mV    879.9mV    484.9mV
25.18ns   189.2mV    259.2mV    180.7mV
31.87ns   130.7mV    138.8mV    125.4mV
99.9ns    122.3mV    125.4mV    123mV
[Rising Waveform]
V_fixture = 0V
V_fixture_min = 0V
V_fixture_max = 0V
R_fixture = 5000Ohm
C_fixture = 0F
|   Time   V(typ)   V(min)   V(max)
0s        42.67mV    42.49mV    43.99mV
4.235ns   40.98mV    41.77mV    41.68mV
5.448ns   40.5mV     41.57mV    -51.87mV
8.269ns   -50mV      41.09mV    275.2mV
12.69ns   454.2mV    -43.17mV   787.5mV
19.12ns   1.085V     642.5mV    1.297V
28.28ns   1.606V     1.379V     1.732V
31.87ns   1.668V     1.522V     1.779V
36.72ns   1.689V     1.576V     1.791V
99.9ns    1.691V     1.59V      1.791V
[Rising Waveform]
V_fixture = 1.8V
V_fixture_min = 1.71V
V_fixture_max = 1.89V
R_fixture = 5000Ohm
C_fixture = 0F
|   Time   V(typ)   V(min)   V(max)
0s        122.1mV    125.2mV    123mV
4.194ns   121.9mV    125.1mV    120.9mV
5.448ns   121.8mV    125mV      48.37mV
8.269ns   74.85mV    124.9mV    601.2mV
12.69ns   877.1mV    117.7mV    1.295V
16.43ns   1.415V     753.1mV    1.738V
19.01ns   1.684V     1.155V     1.865V
22.93ns   1.786V     1.593V     1.887V
28.04ns   1.798V     1.7V       1.889V
99.9ns    1.8V       1.71V      1.89V
[Falling Waveform]
|Gnd
V_fixture = 0V
V_fixture_min = 0V
V_fixture_max = 0V
R_fixture = 5000Ohm
C_fixture = 0F
|   Time   V(typ)   V(min)   V(max)
0s        1.691V     1.59V      1.791V
4.768ns   1.693V     1.591V     1.784V
7.095ns   1.681V     1.592V     1.501V
10.42ns   1.261V     1.577V     850.3mV
14.61ns   513.2mV    1.098V     274.1mV
17.87ns   128.9mV    520.4mV    66.61mV
19.74ns   63.21mV    246.6mV    51.95mV
21.14ns   54.89mV    122mV      49.34mV
25.3ns    47.2mV     50.88mV    46.62mV
99.9ns    42.68mV    42.5mV     43.99mV
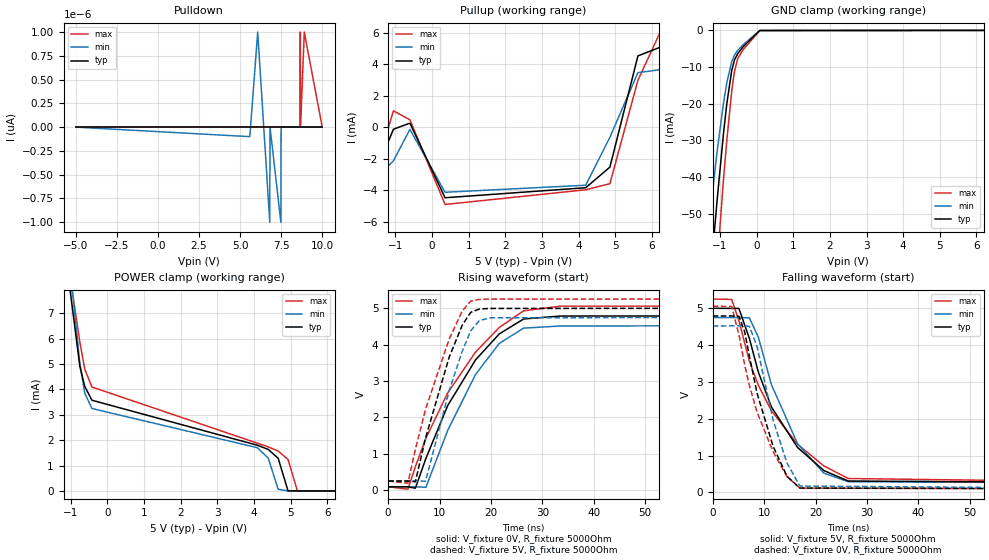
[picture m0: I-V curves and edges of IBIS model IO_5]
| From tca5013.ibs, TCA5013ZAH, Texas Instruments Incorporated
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[Model]   IO_5
Model_type   I/O
Polarity   Non-Inverting
Enable   Active-Low
Vinl = 2
Vinh = 3
Vmeas = 2.5
Vref = 5
Cref = 1pF
Rref = 5000
|   typ   min   max
C_comp   0.937p   0.723p   1.081p
|C_comp (ON state)   0.950p   0.730p   1.090p
|C_comp (OFF state)   0.937p   0.723p   1.081p
[Model spec]
|subparameter
Vinl   2.0   1.9   2.1
Vinh   3.0   2.85   3.15
[Voltage Range]   5   4.75   5.25
[Temperature Range]   27   125   -40
[Pullup Reference]   5   4.75   5.25
[Pulldown Reference]   0   0   0
[Power Clamp Reference]   5   4.75   5.25
[GND Clamp Reference]   0   0   0
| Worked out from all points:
|   slope of the pullup table from 0 to 0.75 V, typ, clamps not added: 577 ohm
|   GND clamp passes 1 mA (typ) near -0.03 V on its own axis
|   falling waveform, V_fixture 5V, R_fixture 5000Ohm: 20-80 % time 9.3ns typ, 7.76ns min, 11.1ns max; typ from 5 V to 0.246 V
|   rising waveform, V_fixture 0V, R_fixture 5000Ohm: 20-80 % time 10.8ns typ, 9.48ns min, 12.2ns max; typ from 0.089 V to 4.79 V
|   rising waveform, V_fixture 5V, R_fixture 5000Ohm: 20-80 % time 6.04ns typ, 5.57ns min, 6.66ns max; typ from 0.246 V to 5 V
|   falling waveform, V_fixture 0V, R_fixture 5000Ohm: 20-80 % time 5.48ns typ, 4.84ns min, 6.45ns max; typ from 4.79 V to 0.089 V
[Pulldown]
|   Voltage   I(typ)   I(min)   I(max)
-5V       0A         0A         0A
5.59V     0A         -100fA     0A
6.07V     0A         1pA        0A
6.805V    0A         -1pA       0A
6.82V     0A         0A         0A
7.48V     0A         -1pA       0A
7.495V    0A         0A         0A
8.65V     0A         0A         0A
8.665V    0A         0A         1pA
8.68V     0A         0A         0A
8.905V    0A         0A         1pA
10V       0A         0A         0A
[GND Clamp]
|   Voltage   I(typ)   I(min)   I(max)
-5V       -2.369A    -1.941A    -2.673A
-2.42V    -219.7mA   -176.2mA   -262.4mA
-1.25V    -66.28mA   -48.1mA    -89.27mA
-1.085V   -47mA      -33.52mA   -64.86mA
-905mV    -28.12mA   -19.9mA    -40.65mA
-815mV    -20.05mA   -14.29mA   -30.07mA
-680mV    -10.97mA   -8.543mA   -16.5mA
-605mV    -8.087mA   -6.745mA   -11.2mA
-515mV    -6.341mA   -5.437mA   -7.665mA
-365mV    -4.434mA   -3.879mA   -5.218mA
85mV      -45.91uA   -55.37uA   -59.48uA
10V       0A         0A         0A
[Pullup]
|   Voltage   I(typ)   I(min)   I(max)
-5V       -18.52mA   -15.06mA   -22.77mA
-1.88V    -4.765mA   -4.059mA   -5.417mA
-1.055V   -132.9uA   -2.139mA   1.036mA
-605mV    253.8uA    -141.3uA   465.6uA
355mV     -4.485mA   -4.136mA   -4.911mA
4.195V    -3.847mA   -3.688mA   -3.977mA
4.855V    -2.541mA   -642uA     -3.593mA
5.62V     4.524mA    3.461mA    2.976mA
6.295V    5.135mA    3.668mA    6.367mA
7.66V     4.946mA    4.221mA    6.395mA
8.065V    608.3uA    1.304mA    556uA
10V       72.03uA    88.68uA    71.46uA
[POWER Clamp]
|   Voltage   I(typ)   I(min)   I(max)
-5V       91.03mA    94.54mA    101.6mA
-1.25V    11.52mA    12.39mA    12.16mA
-1.055V   8.294mA    9.26mA     8.757mA
-755mV    4.909mA    5.036mA    5.866mA
-620mV    4.116mA    3.849mA    4.79mA
-425mV    3.572mA    3.247mA    4.094mA
4.09V     1.8mA      1.703mA    1.881mA
4.39V     1.633mA    1.289mA    1.734mA
4.66V     1.285mA    65.53uA    1.57mA
4.93V     0A         0A         1.237mA
5.185V    0A         0A         0A
10V       0A         0A         0A
[Ramp]
R_load = 5000
|   typ   min   max
dV/dt_r   2.82006/1.0795e-08   2.65774/9.45945e-09   2.98026/1.22453e-08
dV/dt_f   2.85232/9.2946e-09   2.69771/7.74469e-09   3.00156/1.11295e-08
[Falling Waveform]
V_fixture = 5V
V_fixture_min = 4.75V
V_fixture_max = 5.25V
R_fixture = 5000Ohm
C_fixture = 0F
|   Time   V(typ)   V(min)   V(max)
0s        5V         4.75V      5.25V
3.685ns   4.997V     4.746V     5.241V
5.096ns   4.996V     4.745V     4.663V
7.118ns   4.189V     4.743V     3.573V
8.874ns   3.27V      4.218V     2.91V
11.42ns   2.322V     2.927V     2.218V
16.51ns   1.221V     1.321V     1.307V
21.62ns   594.7mV    524.4mV    720.1mV
26.36ns   310.2mV    290.7mV    378.1mV
99.9ns    246mV      253.6mV    247.3mV
[Rising Waveform]
V_fixture = 0V
V_fixture_min = 0V
V_fixture_max = 0V
R_fixture = 5000Ohm
C_fixture = 0F
|   Time   V(typ)   V(min)   V(max)
0s        88.91mV    90.74mV    90.01mV
3.842ns   89.36mV    90.87mV    24.24mV
5.3ns     50.86mV    90.93mV    640.7mV
7.352ns   871.3mV    74.97mV    1.426V
11.58ns   2.32V      1.637V     2.669V
17ns      3.578V     3.176V     3.793V
21.62ns   4.293V     4.031V     4.47V
26.36ns   4.704V     4.452V     4.928V
33.52ns   4.784V     4.511V     5.056V
99.9ns    4.789V     4.52V      5.057V
[Rising Waveform]
V_fixture = 5V
V_fixture_min = 4.75V
V_fixture_max = 5.25V
R_fixture = 5000Ohm
C_fixture = 0F
|   Time   V(typ)   V(min)   V(max)
0s        246mV      253.5mV    247.4mV
3.842ns   246.6mV    253.7mV    188.1mV
5.3ns     228.2mV    253.8mV    1.117V
7.285ns   1.432V     241.9mV    2.224V
11.87ns   3.652V     2.73V      4.147V
14.42ns   4.532V     3.817V     4.925V
16.05ns   4.885V     4.376V     5.192V
17.78ns   4.98V      4.664V     5.242V
20.05ns   4.993V     4.736V     5.251V
99.9ns    5V         4.75V      5.25V
[Falling Waveform]
|Gnd
V_fixture = 0V
V_fixture_min = 0V
V_fixture_max = 0V
R_fixture = 5000Ohm
C_fixture = 0F
|   Time   V(typ)   V(min)   V(max)
0s        4.789V     4.52V      5.057V
3.685ns   4.792V     4.522V     5.049V
5.122ns   4.78V      4.523V     4.272V
6.215ns   4.364V     4.524V     3.463V
7.152ns   3.691V     4.507V     2.897V
8.63ns    2.693V     3.962V     2.178V
11.74ns   1.257V     1.969V     1.109V
14.46ns   437mV      792.2mV    429.1mV
16.96ns   118.5mV    173.2mV    117.7mV
99.9ns    88.91mV    90.74mV    90mV
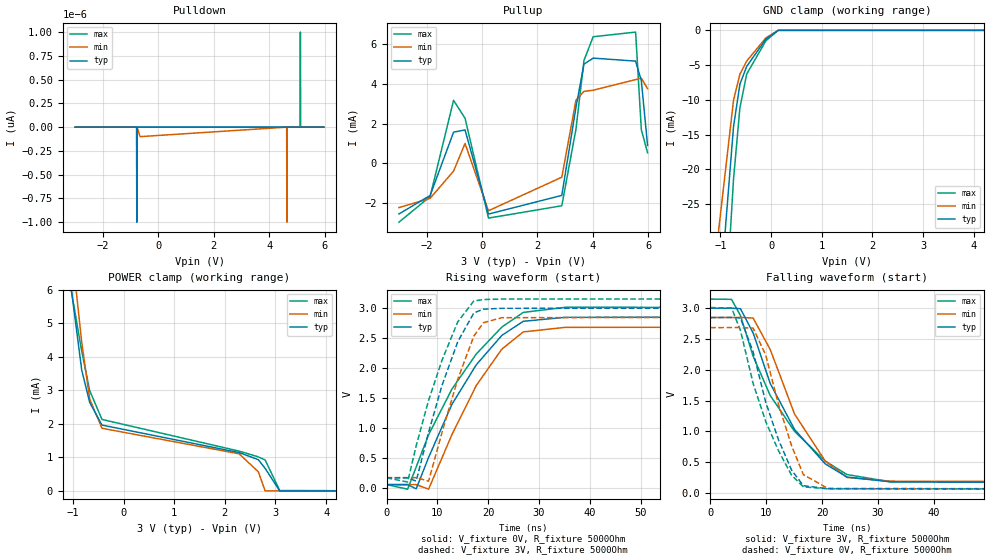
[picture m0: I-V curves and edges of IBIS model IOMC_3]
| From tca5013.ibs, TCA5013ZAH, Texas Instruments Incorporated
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[Model]   IOMC_3
Model_type   I/O
Polarity   Non-Inverting
Enable   Active-Low
Vinl = 0.9
Vinh = 2.1
Vmeas = 1.5
Vref = 3
Cref = 1pF
Rref = 5000
|   typ   min   max
C_comp   0.819p   0.538p   1.031p
|C_comp (ON state)   0.835p   0.552p   1.076p
|C_comp (OFF state)   0.819p   0.538p   1.031p
[Model spec]
|subparameter
Vinl   0.9   0.855   0.945
Vinh   2.1   1.995   2.205
[Voltage Range]   3   2.85   3.15
[Temperature Range]   27   125   -40
[Pullup Reference]   3   2.85   3.15
[Pulldown Reference]   0   0   0
[Power Clamp Reference]   3   2.85   3.15
[GND Clamp Reference]   0   0   0
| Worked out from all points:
|   slope of the pullup table from 0 to 0.45 V, typ, clamps not added: 529 ohm
|   GND clamp passes 1 mA (typ) near -0.07 V on its own axis
|   falling waveform, V_fixture 3V, R_fixture 5000Ohm: 20-80 % time 9.38ns typ, 8.07ns min, 10.9ns max; typ from 3 V to 0.174 V
|   rising waveform, V_fixture 0V, R_fixture 5000Ohm: 20-80 % time 11.1ns typ, 9.84ns min, 12.5ns max; typ from 0.062 V to 2.85 V
|   rising waveform, V_fixture 3V, R_fixture 5000Ohm: 20-80 % time 6.31ns typ, 5.88ns min, 6.86ns max; typ from 0.173 V to 3 V
|   falling waveform, V_fixture 0V, R_fixture 5000Ohm: 20-80 % time 5.67ns typ, 5.13ns min, 6.45ns max; typ from 2.85 V to 0.062 V
[Pulldown]
|   Voltage   I(typ)   I(min)   I(max)
-3V       0A         0A         0A
-786mV    0A         0A         0A
-777mV    -1pA       0A         0A
-768mV    0A         0A         0A
-660mV    0A         -100fA     0A
4.632V    0A         0A         0A
4.641V    0A         -1pA       0A
4.65V     0A         0A         0A
5.118V    0A         0A         0A
5.127V    0A         0A         1pA
5.136V    0A         0A         0A
5.973V    0A         0A         0A
[GND Clamp]
|   Voltage   I(typ)   I(min)   I(max)
-3V       -436.5mA   -240.6mA   -708.5mA
-1.47V    -93.43mA   -68.79mA   -119.6mA
-1.38V    -81.58mA   -60.02mA   -106.3mA
-1.254V   -66.24mA   -47.74mA   -88mA
-1.164V   -55.36mA   -40mA      -74.96mA
-1.029V   -40.15mA   -28.39mA   -56.2mA
-741mV    -13.86mA   -10.06mA   -21.43mA
-615mV    -7.747mA   -6.31mA    -11.13mA
-480mV    -5.182mA   -4.41mA    -6.278mA
-102mV    -1.27mA    -1.087mA   -1.504mA
141mV     0A         0A         0A
5.973V    0A         0A         0A
[Pullup]
|   Voltage   I(typ)   I(min)   I(max)
-3V       -2.533mA   -2.215mA   -2.947mA
-1.875V   -1.607mA   -1.749mA   -1.658mA
-1.029V   1.572mA    -383.4uA   3.167mA
-615mV    1.68mA     1.002mA    2.267mA
231mV     -2.54mA    -2.372mA   -2.741mA
2.877V    -1.604mA   -690.8uA   -2.123mA
3.39V     2.828mA    3.179mA    1.733mA
3.678V    4.982mA    3.616mA    5.172mA
4.011V    5.284mA    3.674mA    6.356mA
5.541V    5.134mA    4.205mA    6.59mA
5.748V    4.153mA    4.275mA    1.689mA
5.973V    905.5uA    3.753mA    534uA
[POWER Clamp]
|   Voltage   I(typ)   I(min)   I(max)
-3V       40.05mA    40.63mA    43.1mA
-1.227V   8.974mA    10.31mA    8.725mA
-1.164V   7.969mA    9.34mA     7.651mA
-1.047V   6.195mA    7.545mA    6.098mA
-826.3mV  3.607mA    4.44mA     4.168mA
-669mV    2.64mA     2.741mA    2.992mA
-426mV    1.963mA    1.868mA    2.131mA
2.283V    1.143mA    1.106mA    1.186mA
2.661V    931.7uA    571.1uA    1.015mA
2.796V    672.4uA    0A         923.2uA
3.084V    0A         0A         11.71uA
5.973V    0A         0A         0A
[Ramp]
R_load = 5000
|   typ   min   max
dV/dt_r   1.67258/1.10908e-08   1.5736/9.85439e-09   1.76966/1.24515e-08
dV/dt_f   1.69575/9.38592e-09   1.60262/8.0549e-09   1.78523/1.0948e-08
[Falling Waveform]
V_fixture = 3V
V_fixture_min = 2.85V
V_fixture_max = 3.15V
R_fixture = 5000Ohm
C_fixture = 0F
|   Time   V(typ)   V(min)   V(max)
0s        3V         2.85V      3.15V
3.795ns   3.002V     2.851V     3.145V
5.399ns   2.993V     2.852V     2.883V
7.671ns   2.6V       2.841V     2.222V
10.72ns   1.78V      2.332V     1.585V
15.09ns   1.031V     1.281V     999.7mV
20.56ns   473.5mV    520.1mV    518.2mV
24.47ns   258.1mV    252.8mV    299mV
32.33ns   180.3mV    191.4mV    179.7mV
99.9ns    173.6mV    178.7mV    174.5mV
[Rising Waveform]
V_fixture = 0V
V_fixture_min = 0V
V_fixture_max = 0V
R_fixture = 5000Ohm
C_fixture = 0F
|   Time   V(typ)   V(min)   V(max)
0s        61.74mV    62.71mV    62.77mV
4.149ns   61.48mV    62.29mV    -14.1mV
5.831ns   -8.897mV   62.12mV    354.6mV
8.27ns    513.2mV    -13.81mV   891.7mV
12.85ns   1.396V     891.8mV    1.65V
17.64ns   2.055V     1.71V      2.235V
22.67ns   2.545V     2.316V     2.683V
26.89ns   2.78V      2.603V     2.928V
35.13ns   2.846V     2.679V     3.013V
99.9ns    2.849V     2.685V     3.012V
[Rising Waveform]
V_fixture = 3V
V_fixture_min = 2.85V
V_fixture_max = 3.15V
R_fixture = 5000Ohm
C_fixture = 0F
|   Time   V(typ)   V(min)   V(max)
0s        173.5mV    178.5mV    174.5mV
4.149ns   173.2mV    178.5mV    105.8mV
5.831ns   120.1mV    178.5mV    708.9mV
8.27ns    931.6mV    119.1mV    1.463V
10.91ns   1.713V     929.7mV    2.132V
14.01ns   2.441V     1.817V     2.771V
17.18ns   2.92V      2.534V     3.119V
19.05ns   2.982V     2.756V     3.142V
22.67ns   2.996V     2.84V      3.15V
99.9ns    3V         2.85V      3.15V
[Falling Waveform]
|Gnd
V_fixture = 0V
V_fixture_min = 0V
V_fixture_max = 0V
R_fixture = 5000Ohm
C_fixture = 0F
|   Time   V(typ)   V(min)   V(max)
0s        2.849V     2.686V     3.012V
3.815ns   2.852V     2.687V     3.005V
5.399ns   2.842V     2.688V     2.641V
7.671ns   2.292V     2.677V     1.778V
9.923ns   1.475V     2.239V     1.16V
12.2ns    865.3mV    1.442V     687.7mV
14.56ns   370.2mV    765.4mV    287.3mV
16.66ns   118.4mV    297.3mV    99.31mV
21.03ns   69.4mV     74.06mV    67.64mV
99.9ns    61.75mV    62.73mV    62.77mV
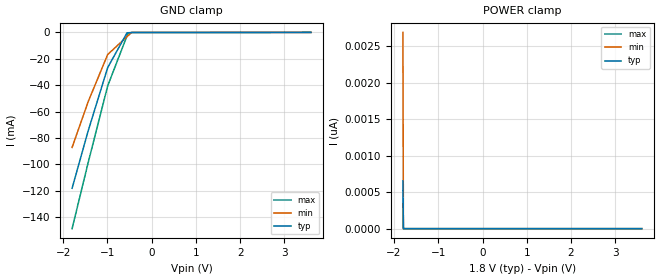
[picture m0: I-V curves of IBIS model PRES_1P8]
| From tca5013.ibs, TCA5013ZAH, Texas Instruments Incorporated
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|   Model PRES
[Model]   PRES_1P8
Model_type   Input
Vinl = .54
Vinh = 1.26
|   typ   min   max
C_comp   0.731p   0.503p   0.930p
[Model spec]
|subparameter
Vinl   0.54   0.495   0.585
Vinh   1.26   1.155   1.365
[Voltage Range]   1.8   1.65   1.95
[Temperature Range]   27   125   -40
[Power Clamp Reference]   1.8   1.65   1.95
[GND Clamp Reference]   0   0   0
[GND Clamp]
|   Voltage   I(typ)   I(min)   I(max)
-1.8V     -118.1mA   -87.14mA   -148.7mA
-1.438V   -74.74mA   -52.62mA   -98.86mA
-995.4mV  -26.66mA   -16.75mA   -40.52mA
-560.5mV  -442.3uA   -3.29mA    -2.763mA
-540mV    -287.3uA   -2.656mA   -983.9uA
-455.4mV  -83.85uA   -38.28uA   -116.5uA
3.6V      0A         0A         0A
[POWER Clamp]
|   Voltage   I(typ)   I(min)   I(max)
-1.8V     653.3pA    2.687nA    519.2pA
-1.789V   0A         0A         0A
-1.784V   0A         0A         0A
3.6V      0A         0A         0A
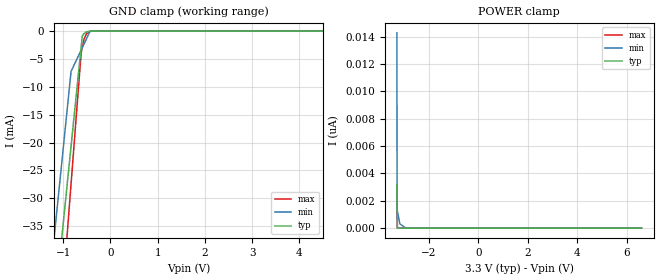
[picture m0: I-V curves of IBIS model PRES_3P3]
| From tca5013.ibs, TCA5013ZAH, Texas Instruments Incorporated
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[Model]   PRES_3P3
Model_type   Input
Vinl = .99
Vinh = 2.31
|   typ   min   max
C_comp   0.731p   0.503p   0.930p
[Model spec]
|subparameter
Vinl   0.99   0.9   1.08
Vinh   2.31   2.1   2.52
[Voltage Range]   3.3   3   3.6
[Temperature Range]   27   125   -40
[Power Clamp Reference]   3.3   3   3.6
[GND Clamp Reference]   0   0   0
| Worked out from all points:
|   GND clamp passes 1 mA (typ) near -0.60 V on its own axis
[GND Clamp]
|   Voltage   I(typ)   I(min)   I(max)
-3.3V     -708.9mA   -336.9mA   -997.1mA
-1.241V   -54.5mA    -41.01mA   -72.15mA
-834.9mV  -20.67mA   -7.233mA   -27.44mA
-623.2mV  -3.028mA   -3.443mA   -4.115mA
-597.9mV  -922.6uA   -2.991mA   -2.864mA
-557.7mV  -417.1uA   -2.272mA   -1.414mA
-508.2mV  -136.7uA   -1.386mA   -473.8uA
-432.1mV  -19.49uA   -22.99uA   -59.04uA
-389.4mV  -5.719uA   -8.688uA   -14.67uA
6.6V      0A         0A         0A
[POWER Clamp]
|   Voltage   I(typ)   I(min)   I(max)
-3.3V     3.177nA    14.27nA    1.839nA
-3.29V    1.588nA    1.375nA    919.4pA
-3.28V    0A         1.273nA    0A
-3.181V   0A         318pA      0A
-2.934V   0A         0A         0A
6.6V      0A         0A         0A
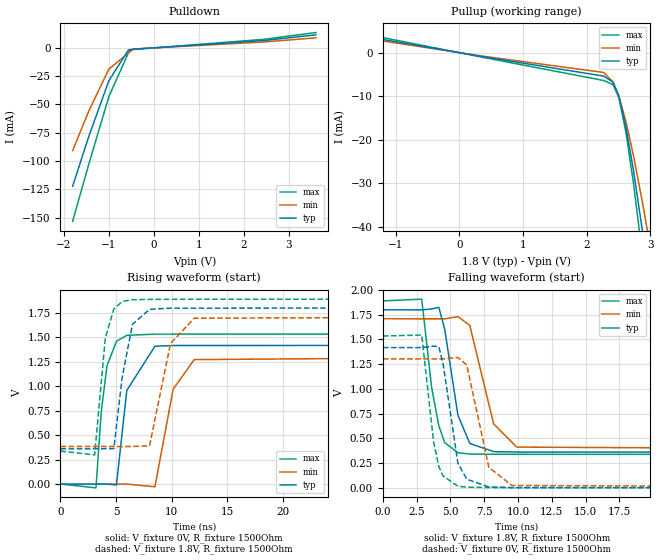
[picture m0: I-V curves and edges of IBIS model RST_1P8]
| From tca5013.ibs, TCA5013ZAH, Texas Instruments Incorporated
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|   Model RST
[Model]   RST_1P8
Model_type   Output
Polarity   Non-Inverting
Vmeas = 0.9
Vref = 1.8
Cref = 1pF
Rref = 1500
|   typ   min   max
C_comp   0.597p   0.445p   0.907p
|C_comp (ON state)   0.597p   0.445p   0.907p
|C_comp (OFF state)   0.592p   0.445p   0.907p
[Voltage Range]   1.8   1.71   1.89
[Temperature Range]   27   125   -40
[Pullup Reference]   1.8   1.71   1.89
[Pulldown Reference]   0   0   0
[Power Clamp Reference]   1.8   1.71   1.89
[GND Clamp Reference]   0   0   0
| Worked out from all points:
|   slope of the pulldown table from 0 to 0.27 V, typ, clamps not added: 375 ohm
|   slope of the pullup table from 0 to 0.27 V, typ, clamps not added: 404 ohm
|   falling waveform, V_fixture 1.8V, R_fixture 1500Ohm: 20-80 % time 1.07ns typ, 1.37ns min, 902ps max; typ from 1.8 V to 0.36 V
|   rising waveform, V_fixture 0V, R_fixture 1500Ohm: 20-80 % time 963ps typ, 1.29ns min, 778ps max; typ from 0 V to 1.42 V
|   rising waveform, V_fixture 1.8V, R_fixture 1500Ohm: 20-80 % time 986ps typ, 1.33ns min, 798ps max; typ from 0.36 V to 1.8 V
|   falling waveform, V_fixture 0V, R_fixture 1500Ohm: 20-80 % time 907ps typ, 1.14ns min, 789ps max; typ from 1.42 V to 0 V
[Pulldown]
|   Voltage   I(typ)   I(min)   I(max)
-1.8V     -122.1mA   -90.78mA   -153.1mA
-1.438V   -77.97mA   -55.57mA   -102.4mA
-995.4mV  -29mA      -18.87mA   -43.08mA
-561mV    -1.931mA   -4.576mA   -4.434mA
-540.6mV  -1.754mA   -3.902mA   -2.613mA
-455.4mV  -1.299mA   -1.1mA     -1.507mA
2.444V    6.382mA    5.106mA    7.438mA
3.6V      11.4mA     8.766mA    13.41mA
[Pullup]
|   Voltage   I(typ)   I(min)   I(max)
-1.8V     4.556mA    4.034mA    5.226mA
354.6mV   -876.4uA   -757.2uA   -1.018mA
2.266V    -5.37mA    -4.54mA    -6.379mA
2.412V    -6.751mA   -6.696mA   -7.333mA
2.504V    -9.959mA   -9.936mA   -10.32mA
2.617V    -17.16mA   -15.91mA   -18.41mA
2.736V    -27.25mA   -23.8mA    -30.25mA
2.871V    -40.6mA    -34.13mA   -46.22mA
2.909V    -44.59mA   -37.22mA   -51mA
2.936V    -47.49mA   -39.48mA   -54.46mA
3.044V    -59.49mA   -48.83mA   -68.7mA
3.6V      -126.6mA   -102.7mA   -146.4mA
[Ramp]
R_load = 1500
|   typ   min   max
dV/dt_r   0.850922/9.62669e-10   0.781924/1.28908e-09   0.920698/7.78019e-10
dV/dt_f   0.864072/1.06687e-09   0.795691/1.36928e-09   0.931568/9.02053e-10
[Falling Waveform]
V_fixture = 1.8V
V_fixture_min = 1.71V
V_fixture_max = 1.89V
R_fixture = 1500Ohm
C_fixture = 0F
|   Time   V(typ)   V(min)   V(max)
0s        1.8V       1.71V      1.89V
2.878ns   1.799V     1.709V     1.908V
3.607ns   1.809V     1.709V     1.019V
4.143ns   1.825V     1.709V     628.7mV
4.576ns   1.607V     1.709V     457.9mV
5.559ns   733.6mV    1.731V     354.7mV
6.437ns   449.3mV    1.642V     342.2mV
8.197ns   366.2mV    647.9mV    339.6mV
9.903ns   362.3mV    412.1mV    339.3mV
49.9ns    359.9mV    383.8mV    337.4mV
[Rising Waveform]
V_fixture = 0V
V_fixture_min = 0V
V_fixture_max = 0V
R_fixture = 1500Ohm
C_fixture = 0F
|   Time   V(typ)   V(min)   V(max)
0s        8.617nV    368.3nV    4.095nV
3.198ns   -47.95uV   -19.22uV   -38.72mV
3.675ns   432uV      -22.15uV   746.4mV
4.19ns    -5.268uV   -25.3uV    1.209V
5.038ns   -8.875mV   -30.49uV   1.459V
5.971ns   957mV      -36.21uV   1.52V
8.503ns   1.409V     -27.69mV   1.532V
10.14ns   1.416V     969.7mV    1.532V
12.04ns   1.416V     1.272V     1.533V
49.9ns    1.418V     1.303V     1.534V
[Rising Waveform]
V_fixture = 1.8V
V_fixture_min = 1.71V
V_fixture_max = 1.89V
R_fixture = 1500Ohm
C_fixture = 0F
|   Time   V(typ)   V(min)   V(max)
0s        359.9mV    383.8mV    337.4mV
3.077ns   359.8mV    383.8mV    298.1mV
4.037ns   361.6mV    383.8mV    1.493V
4.799ns   361.7mV    383.8mV    1.788V
5.559ns   1.093V     383.8mV    1.866V
6.482ns   1.632V     384.4mV    1.884V
8.018ns   1.786V     392.3mV    1.887V
9.903ns   1.798V     1.436V     1.888V
12.04ns   1.798V     1.695V     1.889V
49.9ns    1.8V       1.71V      1.89V
[Falling Waveform]
|Gnd
V_fixture = 0V
V_fixture_min = 0V
V_fixture_max = 0V
R_fixture = 1500Ohm
C_fixture = 0F
|   Time   V(typ)   V(min)   V(max)
0s        1.418V     1.303V     1.535V
2.878ns   1.418V     1.303V     1.545V
3.755ns   1.433V     1.303V     467.6mV
4.143ns   1.428V     1.303V     215.9mV
4.456ns   1.257V     1.303V     119.7mV
5.559ns   247.8mV    1.318V     16.42mV
6.21ns    87.26mV    1.243V     7.137mV
7.844ns   9.342mV    208.2mV    2.876mV
9.545ns   3.061mV    24.44mV    2.026mV
49.9ns    9.394uV    57.41uV    335.1nV
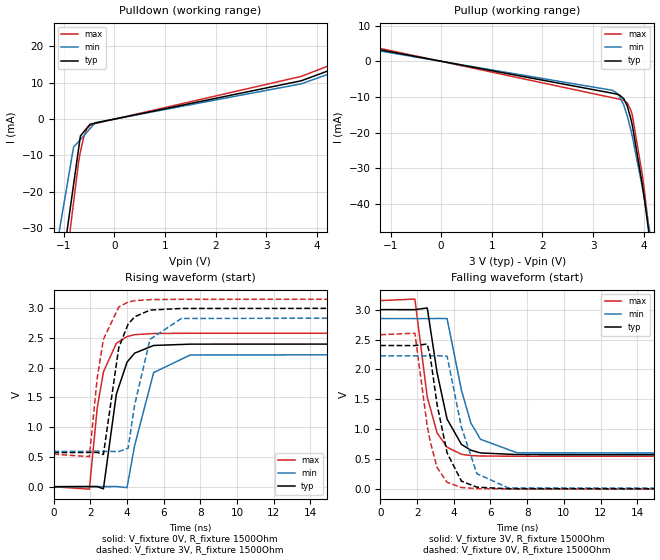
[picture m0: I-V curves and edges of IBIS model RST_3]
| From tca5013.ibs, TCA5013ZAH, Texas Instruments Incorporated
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[Model]   RST_3
Model_type   Output
Polarity   Non-Inverting
Vmeas = 1.5
Vref = 3
Cref = 1pF
Rref = 1500
|   typ   min   max
C_comp   0.819p   0.538p   1.031p
|C_comp (ON state)   0.835p   0.552p   1.076p
|C_comp (OFF state)   0.819p   0.538p   1.031p
[Voltage Range]   3   2.85   3.15
[Temperature Range]   27   125   -40
[Pullup Reference]   3   2.85   3.15
[Pulldown Reference]   0   0   0
[Power Clamp Reference]   3   2.85   3.15
[GND Clamp Reference]   0   0   0
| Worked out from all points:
|   slope of the pulldown table from 0 to 0.45 V, typ, clamps not added: 355 ohm
|   slope of the pullup table from 0 to 0.45 V, typ, clamps not added: 376 ohm
|   falling waveform, V_fixture 3V, R_fixture 1500Ohm: 20-80 % time 921ps typ, 1.03ns min, 840ps max; typ from 3 V to 0.573 V
|   rising waveform, V_fixture 0V, R_fixture 1500Ohm: 20-80 % time 789ps typ, 912ps min, 710ps max; typ from 0 V to 2.4 V
|   rising waveform, V_fixture 3V, R_fixture 1500Ohm: 20-80 % time 773ps typ, 875ps min, 702ps max; typ from 0.573 V to 3 V
|   falling waveform, V_fixture 0V, R_fixture 1500Ohm: 20-80 % time 905ps typ, 990ps min, 841ps max; typ from 2.4 V to 0 V
[Pulldown]
|   Voltage   I(typ)   I(min)   I(max)
-3V       -433.2mA   -218.3mA   -707.4mA
-1.083V   -45.68mA   -30.56mA   -54.35mA
-804mV    -18.01mA   -7.704mA   -22.91mA
-705mV    -8.189mA   -6.156mA   -11.76mA
-669mV    -4.618mA   -5.593mA   -8.946mA
-606mV    -3.551mA   -4.607mA   -5.049mA
-543mV    -2.485mA   -3.622mA   -2.725mA
-480mV    -1.418mA   -2.636mA   -1.739mA
-372.2mV  -1.054mA   -950.2uA   -1.19mA
3.696V    10.57mA    9.732mA    11.78mA
4.713V    15.8mA     14.78mA    17.24mA
6V        23.09mA    21.22mA    25.39mA
[Pullup]
|   Voltage   I(typ)   I(min)   I(max)
-3V       8.039mA    7.259mA    9.094mA
3.39V     -8.933mA   -8.12mA    -10.2mA
3.48V     -9.22mA    -8.998mA   -10.47mA
3.525V    -9.453mA   -9.816mA   -10.61mA
3.606V    -10.43mA   -12.21mA   -10.94mA
3.678V    -12.56mA   -15.38mA   -11.66mA
3.75V     -16.23mA   -19.38mA   -13.78mA
3.777V    -17.97mA   -21.05mA   -15.11mA
3.975V    -34.64mA   -35.38mA   -31.9mA
4.02V     -39.09mA   -39.03mA   -36.84mA
4.227V    -61.38mA   -57.12mA   -62.4mA
6V        -434.7mA   -255.9mA   -565.9mA
[Ramp]
R_load = 1500
|   typ   min   max
dV/dt_r   1.43976/7.89518e-10   1.33645/9.11762e-10   1.54821/7.09505e-10
dV/dt_f   1.45617/9.21328e-10   1.35418/1.03287e-09   1.56181/8.40564e-10
[Falling Waveform]
V_fixture = 3V
V_fixture_min = 2.85V
V_fixture_max = 3.15V
R_fixture = 1500Ohm
C_fixture = 0F
|   Time   V(typ)   V(min)   V(max)
0s        3V         2.85V      3.15V
1.88ns    2.999V     2.849V     3.176V
2.554ns   3.027V     2.849V     1.54V
3.09ns    1.946V     2.852V     940.2mV
3.635ns   1.171V     2.85V      700.2mV
4.42ns    746.9mV    1.65V      582.7mV
4.934ns   650.6mV    1.103V     561.6mV
5.457ns   605.6mV    833.3mV    554mV
7.451ns   577.6mV    607.3mV    550.2mV
49.9ns    573mV      593mV      547mV
[Rising Waveform]
V_fixture = 0V
V_fixture_min = 0V
V_fixture_max = 0V
R_fixture = 1500Ohm
C_fixture = 0F
|   Time   V(typ)   V(min)   V(max)
0s        14.08nV    515.2nV    6.668nV
1.953ns   2.47mV     1.28mV     -41.51mV
2.381ns   1.889mV    1.56mV     1.319V
2.72ns    -36.51mV   1.782mV    1.926V
3.424ns   1.553V     2.243mV    2.407V
4.006ns   2.09V      -15.28mV   2.52V
4.42ns    2.242V     689.5mV    2.552V
5.457ns   2.371V     1.915V     2.572V
7.451ns   2.393V     2.211V     2.576V
49.9ns    2.4V       2.227V     2.58V
[Rising Waveform]
V_fixture = 3V
V_fixture_min = 2.85V
V_fixture_max = 3.15V
R_fixture = 1500Ohm
C_fixture = 0F
|   Time   V(typ)   V(min)   V(max)
0s        573mV      593mV      546.9mV
1.953ns   575.2mV    593.9mV    504.3mV
2.381ns   575.2mV    594.1mV    1.824V
2.72ns    540.6mV    594.3mV    2.474V
3.555ns   2.332V     589.2mV    3.016V
4.065ns   2.728V     645.5mV    3.099V
4.42ns    2.852V     1.371V     3.123V
5.26ns    2.965V     2.473V     3.141V
6.97ns    2.992V     2.824V     3.146V
49.9ns    3V         2.85V      3.15V
[Falling Waveform]
|Gnd
V_fixture = 0V
V_fixture_min = 0V
V_fixture_max = 0V
R_fixture = 1500Ohm
C_fixture = 0F
|   Time   V(typ)   V(min)   V(max)
0s        2.4V       2.227V     2.58V
1.88ns    2.399V     2.227V     2.606V
2.554ns   2.425V     2.226V     1.051V
2.72ns    2.217V     2.226V     790.6mV
3.09ns    1.413V     2.23V      360.7mV
3.635ns   607mV      2.222V     114.6mV
4.42ns    133.7mV    1.032V     27.95mV
5.26ns    33.77mV    258.8mV    9.152mV
6.97ns    6.215mV    21.46mV    4.156mV
49.9ns    10.2uV     60.21uV    406.8nV
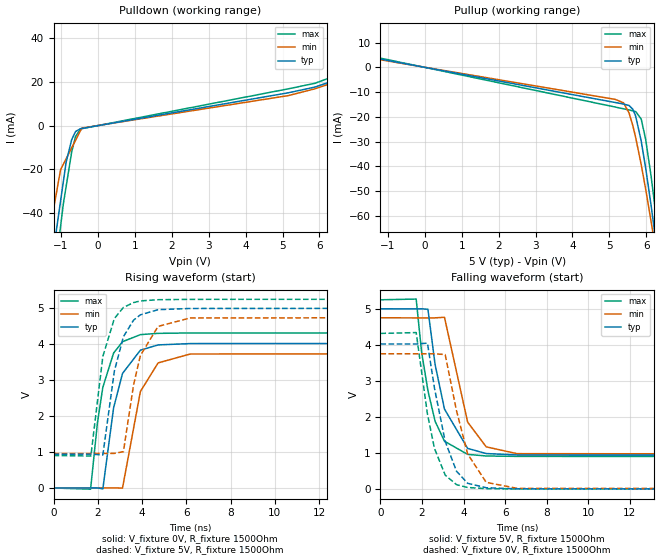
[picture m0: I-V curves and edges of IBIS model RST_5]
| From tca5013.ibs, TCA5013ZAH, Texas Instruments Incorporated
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[Model]   RST_5
Model_type   Output
Polarity   Non-Inverting
Vmeas = 2.5
Vref = 5
Cref = 1pF
Rref = 1500
|   typ   min   max
C_comp   0.937p   0.723p   1.081p
|C_comp (ON state)   0.950p   0.730p   1.090p
|C_comp (OFF state)   0.937p   0.723p   1.081p
[Voltage Range]   5   4.75   5.25
[Temperature Range]   27   125   -40
[Pullup Reference]   5   4.75   5.25
[Pulldown Reference]   0   0   0
[Power Clamp Reference]   5   4.75   5.25
[GND Clamp Reference]   0   0   0
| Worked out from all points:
|   slope of the pulldown table from 0 to 0.75 V, typ, clamps not added: 348 ohm
|   slope of the pullup table from 0 to 0.75 V, typ, clamps not added: 364 ohm
|   falling waveform, V_fixture 5V, R_fixture 1500Ohm: 20-80 % time 886ps typ, 957ps min, 819ps max; typ from 5 V to 0.939 V
|   rising waveform, V_fixture 0V, R_fixture 1500Ohm: 20-80 % time 734ps typ, 792ps min, 680ps max; typ from 0 V to 4.03 V
|   rising waveform, V_fixture 5V, R_fixture 1500Ohm: 20-80 % time 712ps typ, 761ps min, 664ps max; typ from 0.938 V to 5 V
|   falling waveform, V_fixture 0V, R_fixture 1500Ohm: 20-80 % time 930ps typ, 1ns min, 858ps max; typ from 4.03 V to 0 V
[Pulldown]
|   Voltage   I(typ)   I(min)   I(max)
-5V       -2.369A    -1.94A     -2.673A
-2.24V    -179mA     -136.9mA   -214.9mA
-1.01V    -34.47mA   -20.15mA   -46.08mA
-935mV    -25.66mA   -17.68mA   -35.78mA
-860mV    -16.84mA   -15.2mA    -27.92mA
-710mV    -6.512mA   -10.25mA   -12.2mA
-605mV    -2.751mA   -6.781mA   -5.021mA
-470mV    -1.451mA   -2.323mA   -1.673mA
-425mV    -1.308mA   -1.137mA   -1.406mA
5.155V    14.9mA     13.62mA    16.71mA
5.875V    17.5mA     16.73mA    19.22mA
10V       41.22mA    39.48mA    45.03mA
[Pullup]
|   Voltage   I(typ)   I(min)   I(max)
-5V       13.84mA    12.67mA    15.58mA
5.155V    -14.18mA   -12.91mA   -16.01mA
5.38V     -14.8mA    -14.29mA   -16.72mA
5.53V     -15.38mA   -18.35mA   -17.2mA
5.635V    -16.9mA    -23.61mA   -17.54mA
5.71V     -19.68mA   -28.3mA    -17.85mA
5.86V     -29.75mA   -39.26mA   -20.86mA
5.98V     -40.55mA   -49.13mA   -28.99mA
6.13V     -56mA      -62.46mA   -44.16mA
6.25V     -69.36mA   -73.74mA   -58.61mA
6.28V     -72.81mA   -76.63mA   -62.42mA
10V       -2.369A    -2.186A    -2.426A
[Ramp]
R_load = 1500
|   typ   min   max
dV/dt_r   2.41502/7.34103e-10   2.25122/7.92056e-10   2.59046/6.80889e-10
dV/dt_f   2.43687/8.85756e-10   2.27485/9.57331e-10   2.60862/8.19493e-10
[Falling Waveform]
V_fixture = 5V
V_fixture_min = 4.75V
V_fixture_max = 5.25V
R_fixture = 1500Ohm
C_fixture = 0F
|   Time   V(typ)   V(min)   V(max)
0s        5V         4.75V      5.25V
1.721ns   4.999V     4.749V     5.27V
1.983ns   5V         4.749V     3.799V
2.287ns   4.987V     4.749V     2.731V
2.631ns   3.459V     4.749V     1.884V
3.083ns   2.221V     4.765V     1.329V
4.198ns   1.13V      1.859V     964.4mV
5.092ns   987.3mV    1.173V     920mV
6.577ns   948mV      984.2mV    908.6mV
49.9ns    938.6mV    958.6mV    902.3mV
[Rising Waveform]
V_fixture = 0V
V_fixture_min = 0V
V_fixture_max = 0V
R_fixture = 1500Ohm
C_fixture = 0F
|   Time   V(typ)   V(min)   V(max)
0s        28.57nV    948.8nV    11.18nV
1.675ns   2.43mV     1.856mV    -32.56mV
1.983ns   2.876mV    2.196mV    1.81V
2.228ns   -25.31mV   2.467mV    2.799V
2.714ns   2.227V     3.006mV    3.75V
3.117ns   3.183V     -1.852mV   4.065V
3.925ns   3.83V      2.681V     4.262V
4.725ns   3.976V     3.476V     4.297V
6.175ns   4.013V     3.723V     4.308V
49.9ns    4.025V     3.752V     4.317V
[Rising Waveform]
V_fixture = 5V
V_fixture_min = 4.75V
V_fixture_max = 5.25V
R_fixture = 1500Ohm
C_fixture = 0F
|   Time   V(typ)   V(min)   V(max)
0s        938.4mV    958.3mV    902mV
1.687ns   940.3mV    959.8mV    889mV
2.228ns   916.8mV    960.3mV    3.657V
2.748ns   3.246V     960.7mV    4.708V
3.157ns   4.203V     1.011V     5.017V
3.616ns   4.664V     2.866V     5.152V
3.925ns   4.812V     3.684V     5.198V
4.725ns   4.955V     4.491V     5.232V
6.175ns   4.989V     4.725V     5.242V
49.9ns    5V         4.75V      5.25V
[Falling Waveform]
|Gnd
V_fixture = 0V
V_fixture_min = 0V
V_fixture_max = 0V
R_fixture = 1500Ohm
C_fixture = 0F
|   Time   V(typ)   V(min)   V(max)
0s        4.025V     3.752V     4.318V
1.721ns   4.024V     3.752V     4.341V
2.264ns   4.048V     3.752V     2.079V
2.603ns   2.797V     3.752V     1.129V
3.117ns   1.326V     3.732V     391.1mV
3.662ns   498.1mV    2.176V     124.7mV
4.198ns   162.8mV    976.1mV    46.5mV
5.092ns   38.84mV    188.8mV    14.43mV
6.577ns   9.343mV    23.36mV    6.667mV
49.9ns    13.22uV    76.52uV    545.2nV
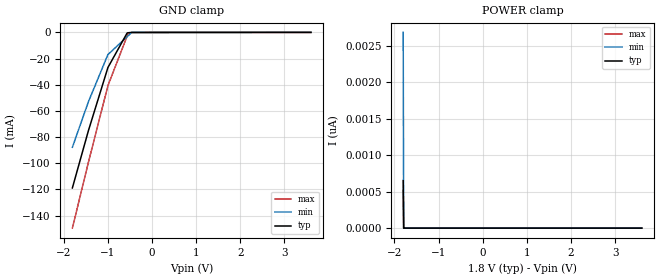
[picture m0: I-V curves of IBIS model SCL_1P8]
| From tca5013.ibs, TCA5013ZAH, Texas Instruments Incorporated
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|   Model SCL
[Model]   SCL_1P8
Model_type   Input
Vinl = .36
Vinh = 1.44
|   typ   min   max
C_comp   0.731p   0.503p   0.930p
[Model spec]
|subparameter
Vinl   0.36   0.33   0.39
Vinh   1.44   1.32   1.56
[Voltage Range]   1.8   1.65   1.95
[Temperature Range]   27   125   -40
[Power Clamp Reference]   1.8   1.65   1.95
[GND Clamp Reference]   0   0   0
[GND Clamp]
|   Voltage   I(typ)   I(min)   I(max)
-1.8V     -118.9mA   -87.82mA   -149.6mA
-1.438V   -75.21mA   -53.07mA   -99.38mA
-995.4mV  -26.83mA   -16.94mA   -40.69mA
-560.4mV  -443uA     -3.326mA   -2.77mA
-539.9mV  -286.2uA   -2.685mA   -982.8uA
-455.4mV  -36.3uA    -38.91uA   -116.5uA
3.6V      0A         0A         0A
[POWER Clamp]
|   Voltage   I(typ)   I(min)   I(max)
-1.8V     653.3pA    2.687nA    519.2pA
-1.789V   0A         0A         0A
-1.784V   0A         0A         0A
3.6V      0A         0A         0A
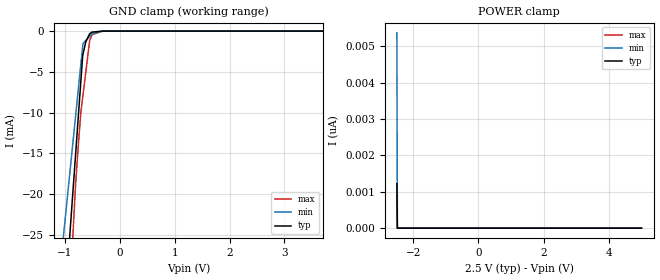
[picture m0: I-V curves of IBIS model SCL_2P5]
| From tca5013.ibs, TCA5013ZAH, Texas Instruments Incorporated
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[Model]   SCL_2P5
Model_type   Input
Vinl = .5
Vinh = 2.0
|   typ   min   max
C_comp   0.731p   0.503p   0.930p
[Model spec]
|subparameter
Vinl   0.5   0.45   0.55
Vinh   2.0   1.8   2.2
[Voltage Range]   2.5   2.25   2.75
[Temperature Range]   27   125   -40
[Power Clamp Reference]   2.5   2.25   2.75
[GND Clamp Reference]   0   0   0
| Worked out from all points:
|   GND clamp passes 1 mA (typ) near -0.60 V on its own axis
[GND Clamp]
|   Voltage   I(typ)   I(min)   I(max)
-2.5V     -205.3mA   -160.1mA   -266.8mA
-1.42V    -73.07mA   -51.41mA   -96.88mA
-803.1mV  -15.1mA    -10.4mA    -18.77mA
-752.5mV  -10.34mA   -7.035mA   -13.88mA
-707.5mV  -6.116mA   -4.043mA   -9.966mA
-675mV    -3.058mA   -1.88mA    -8.18mA
-670mV    -2.868mA   -1.55mA    -7.908mA
-617.5mV  -1.308mA   -1.161mA   -5.026mA
-546.5mV  -329.5uA   -635.3uA   -1.128mA
-505mV    -126.8uA   -328.1uA   -438uA
-310mV    -483nA     -1.285uA   -731.6nA
5V        0A         0A         0A
[POWER Clamp]
|   Voltage   I(typ)   I(min)   I(max)
-2.5V     1.225nA    5.366nA    843.3pA
-2.485V   0A         0A         0A
-2.478V   0A         0A         0A
5V        0A         0A         0A
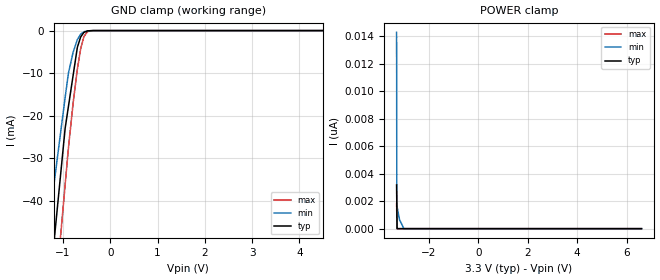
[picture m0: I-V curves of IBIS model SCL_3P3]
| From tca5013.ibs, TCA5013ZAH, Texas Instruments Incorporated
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[Model]   SCL_3P3
Model_type   Input
Vinl = .66
Vinh = 2.64
|   typ   min   max
C_comp   0.731p   0.503p   0.930p
[Model spec]
|subparameter
Vinl   0.66   0.6   0.72
Vinh   2.64   2.4   2.88
[Voltage Range]   3.3   3   3.6
[Temperature Range]   27   125   -40
[Power Clamp Reference]   3.3   3   3.6
[GND Clamp Reference]   0   0   0
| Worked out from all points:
|   GND clamp passes 1 mA (typ) near -0.60 V on its own axis
[GND Clamp]
|   Voltage   I(typ)   I(min)   I(max)
-3.3V     -709mA     -337.3mA   -997.1mA
-1.766V   -114.6mA   -85.48mA   -145mA
-1.191V   -49.75mA   -36.09mA   -65.9mA
-953.7mV  -22.89mA   -15.65mA   -36.08mA
-884.4mV  -17.79mA   -9.978mA   -27.5mA
-785.4mV  -10.51mA   -5.079mA   -17.01mA
-696.3mV  -3.963mA   -2.128mA   -9.066mA
-627mV    -1.53mA    -866.2uA   -4.332mA
-557.7mV  -418.1uA   -287.5uA   -1.415mA
-478.5mV  -65.95uA   -63.53uA   -221uA
-369.6mV  -3.161uA   -5.476uA   -7.293uA
6.6V      0A         0A         0A
[POWER Clamp]
|   Voltage   I(typ)   I(min)   I(max)
-3.3V     3.177nA    14.27nA    1.839nA
-3.29V    1.588nA    1.698nA    919.4pA
-3.28V    0A         1.596nA    0A
-3.181V   0A         641.3pA    0A
-3.003V   0A         0A         0A
6.6V      0A         0A         0A
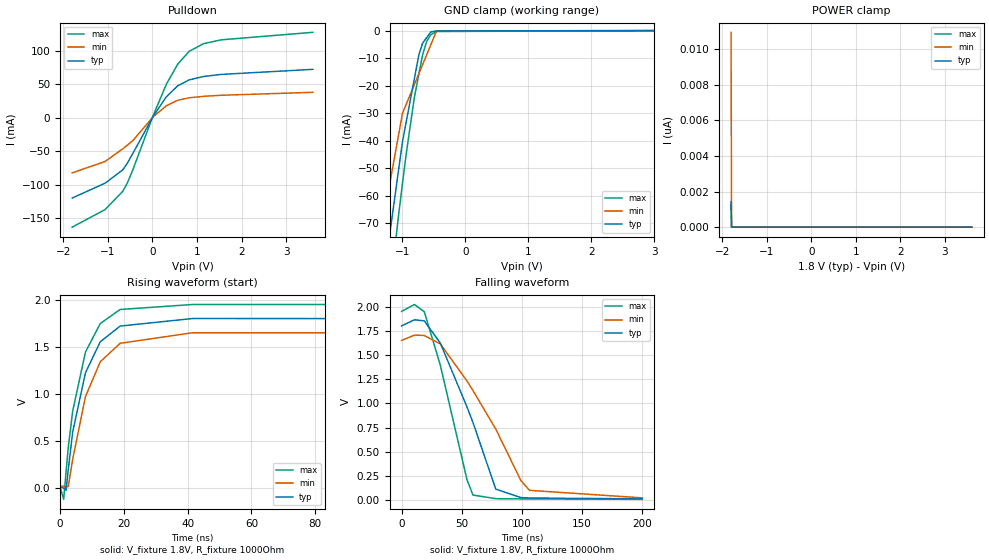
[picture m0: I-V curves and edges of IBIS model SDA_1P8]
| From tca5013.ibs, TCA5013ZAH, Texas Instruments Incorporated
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|   Model SDA
[Model]   SDA_1P8
Model_type   I/O_open_drain
Polarity   Non-Inverting
Enable   Active-Low
Vinl = .4
Vinh = 1.4
Vmeas = 0.9
Vref = 1.8
Cref = 15pF
Rref = 1000
|   typ   min   max
C_comp   1.983p   1.522p   2.375p
|C_comp (Low state)   1.922p   1.492p   2.318p
|C_comp (High state)   1.983p   1.522p   2.375p
[Voltage Range]   1.8   1.65   1.95
[Temperature Range]   27   125   -40
[Pullup Reference]   1.8   1.65   1.95
[Pulldown Reference]   0   0   0
[Power Clamp Reference]   1.8   1.65   1.95
[GND Clamp Reference]   0   0   0
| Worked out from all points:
|   slope of the pulldown table from 0 to 0.27 V, typ, clamps not added: 9.79 ohm
|   GND clamp passes 1 mA (typ) near -0.56 V on its own axis
|   falling waveform, V_fixture 1.8V, R_fixture 1000Ohm: 20-80 % time 32.3ns typ, 43.8ns min, 22.8ns max; typ from 1.8 V to 0.014 V
|   rising waveform, V_fixture 1.8V, R_fixture 1000Ohm: 20-80 % time 7.44ns typ, 8.15ns min, 6.86ns max; typ from 0.013 V to 1.8 V
[Pulldown]
|   Voltage   I(typ)   I(min)   I(max)
-1.8V     -120.2mA   -82.58mA   -163.7mA
-1.061V   -97.92mA   -65.51mA   -137.4mA
-666mV    -78.14mA   -46.63mA   -110.2mA
-563.4mV  -68.16mA   -41.29mA   -97.96mA
-433.8mV  -52.93mA   -33.92mA   -77.08mA
14.4mV    1.688mA    1.006mA    2.584mA
316.8mV   31.48mA    17.93mA    50.46mA
570.6mV   47.69mA    25.99mA    80.11mA
824.4mV   56.41mA    29.68mA    99.07mA
1.148V    61.47mA    31.85mA    110.5mA
1.543V    64.59mA    33.41mA    116.3mA
3.6V      72.17mA    37.86mA    127.5mA
[GND Clamp]
|   Voltage   I(typ)   I(min)   I(max)
-1.8V     -181.3mA   -139.4mA   -225mA
-1.438V   -114mA     -86.16mA   -145.5mA
-1.061V   -51.26mA   -38.38mA   -67.81mA
-995.4mV  -40.39mA   -30.1mA    -55.48mA
-936mV    -33.17mA   -26.8mA    -44.8mA
-806.4mV  -17.43mA   -19.62mA   -24.21mA
-736.2mV  -8.902mA   -15.73mA   -15.92mA
-676.8mV  -4.634mA   -12.44mA   -8.902mA
-612mV    -2.581mA   -8.843mA   -3.993mA
-547.2mV  -528.6uA   -5.251mA   -1.543mA
-455.4mV  -145.3uA   -162.8uA   -349uA
3.6V      0A         0A         0A
[POWER Clamp]
|   Voltage   I(typ)   I(min)   I(max)
-1.8V     1.422nA    10.94nA    1.24nA
-1.789V   0A         0A         0A
-1.784V   0A         0A         0A
3.6V      0A         0A         0A
[Ramp]
R_load = 1000
|   typ   min   max
dV/dt_r   1.07192/7.42432e-09   0.976907/8.16369e-09   1.16468/6.83514e-09
dV/dt_f   1.07164/3.23207e-08   0.975589/4.38394e-08   1.16463/2.28244e-08
[Falling Waveform]
V_fixture = 1.8V
V_fixture_min = 1.65V
V_fixture_max = 1.95V
R_fixture = 1000Ohm
C_fixture = 0F
|   Time   V(typ)   V(min)   V(max)
0s        1.8V       1.65V      1.95V
10.7ns    1.863V     1.705V     2.021V
18.82ns   1.852V     1.701V     1.946V
32.11ns   1.623V     1.614V     1.396V
54.32ns   962.2mV    1.231V     209.7mV
59.28ns   801.9mV    1.132V     53.34mV
78.2ns    114.6mV    734.5mV    15.87mV
99.06ns   26.95mV    203.1mV    13.54mV
106.2ns   22.68mV    101.7mV    13.21mV
199.9ns   13.94mV    24.01mV    8.955mV
[Rising Waveform]
V_fixture = 1.8V
V_fixture_min = 1.65V
V_fixture_max = 1.95V
R_fixture = 1000Ohm
C_fixture = 0F
|   Time   V(typ)   V(min)   V(max)
0s        13.46mV    21.82mV    8.864mV
1.11ns    59.33uV    21.5mV     -118.9mV
1.838ns   -23.26mV   13.67mV    166mV
2.521ns   189.7mV    16.06mV    425.6mV
3.93ns    595.3mV    305.9mV    817.4mV
7.938ns   1.225V     972mV      1.445V
12.58ns   1.554V     1.342V     1.748V
18.82ns   1.721V     1.538V     1.897V
41.52ns   1.801V     1.65V      1.95V
199.9ns   1.8V       1.65V      1.95V
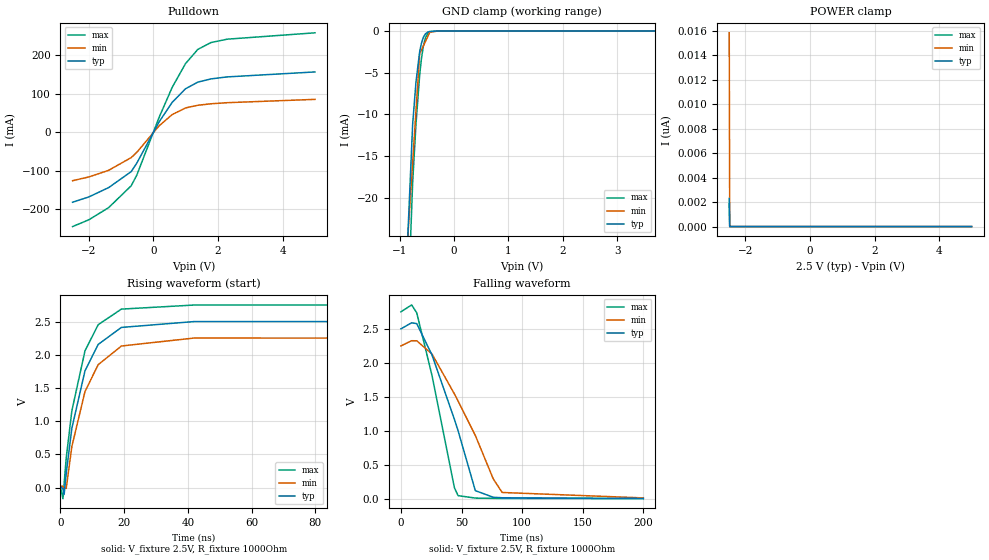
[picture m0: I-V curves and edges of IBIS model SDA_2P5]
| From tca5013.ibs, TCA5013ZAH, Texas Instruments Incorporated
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[Model]   SDA_2P5
Model_type   I/O_open_drain
Polarity   Non-Inverting
Enable   Active-Low
Vinl = .4
Vinh = 1.4
Vmeas = 1.25
Vref = 2.5
Cref = 15pF
Rref = 1000
|   typ   min   max
C_comp   2.075p   1.623p   2.368p
|C_comp (Low state)   2.075p   1.623p   2.368p
|C_comp (High state)   2.147p   1.701p   2.380p
[Voltage Range]   2.5   2.25   2.75
[Temperature Range]   27   125   -40
[Pullup Reference]   2.5   2.25   2.75
[Pulldown Reference]   0   0   0
[Power Clamp Reference]   2.5   2.25   2.75
[GND Clamp Reference]   0   0   0
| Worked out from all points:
|   slope of the pulldown table from 0 to 0.375 V, typ, clamps not added: 7.02 ohm
|   GND clamp passes 1 mA (typ) near -0.58 V on its own axis
|   falling waveform, V_fixture 2.5V, R_fixture 1000Ohm: 20-80 % time 27.3ns typ, 36.3ns min, 19.8ns max; typ from 2.5 V to 0.013 V
|   rising waveform, V_fixture 2.5V, R_fixture 1000Ohm: 20-80 % time 7.43ns typ, 8.14ns min, 6.83ns max; typ from 0.013 V to 2.5 V
[Pulldown]
|   Voltage   I(typ)   I(min)   I(max)
-2.5V     -181.7mA   -125.8mA   -245mA
-1.998V   -168mA     -116.1mA   -227.4mA
-1.383V   -143.7mA   -98.82mA   -195.7mA
-685mV    -102.1mA   -65.73mA   -138.9mA
-512.5mV  -80.06mA   -52.12mA   -111.3mA
177.5mV   26.85mA    16.68mA    38.71mA
582.5mV   77.74mA    46.04mA    116.7mA
995mV     113mA      63.18mA    178.4mA
1.377V    130.3mA    70.2mA     215.3mA
1.782V    138.6mA    73.95mA    233mA
2.285V    143.8mA    76.84mA    241.8mA
5V        156.7mA    85.44mA    258.3mA
[GND Clamp]
|   Voltage   I(typ)   I(min)   I(max)
-2.5V     -317.5mA   -250.5mA   -382.8mA
-1.202V   -77.81mA   -60.21mA   -95.93mA
-761.6mV  -11.21mA   -15.75mA   -18.22mA
-700mV    -6.096mA   -9.541mA   -11.15mA
-632.5mV  -2.49mA    -2.734mA   -5.307mA
-602.5mV  -1.522mA   -2.317mA   -3.455mA
-565mV    -755.7uA   -1.797mA   -1.807mA
-527.5mV  -345.5uA   -1.276mA   -823.7uA
-482.5mV  -123.8uA   -651.5uA   -271.1uA
-445mV    -49.42uA   -130.9uA   -95.06uA
-302.5mV  -888nA     -6.46uA    -583.5nA
5V        0A         0A         0A
[POWER Clamp]
|   Voltage   I(typ)   I(min)   I(max)
-2.5V     2.293nA    15.84nA    1.852nA
-2.485V   0A         0A         0A
-2.478V   0A         0A         0A
5V        0A         0A         0A
[Ramp]
R_load = 1000
|   typ   min   max
dV/dt_r   1.49204/7.41855e-09   1.33789/8.07755e-09   1.64432/6.83213e-09
dV/dt_f   1.49191/2.73168e-08   1.33736/3.63167e-08   1.6443/1.97752e-08
[Falling Waveform]
V_fixture = 2.5V
V_fixture_min = 2.25V
V_fixture_max = 2.75V
R_fixture = 1000Ohm
C_fixture = 0F
|   Time   V(typ)   V(min)   V(max)
0s        2.5V       2.25V      2.75V
8.851ns   2.589V     2.326V     2.851V
13.05ns   2.577V     2.325V     2.736V
25.64ns   2.117V     2.131V     1.817V
44.13ns   1.173V     1.546V     169.8mV
47.13ns   1.008V     1.443V     54.5mV
61.38ns   127.6mV    937.2mV    18.41mV
76.12ns   30.64mV    301.6mV    14.12mV
83.5ns    22.98mV    100.7mV    13.85mV
199.9ns   13.47mV    21.06mV    9.507mV
[Rising Waveform]
V_fixture = 2.5V
V_fixture_min = 2.25V
V_fixture_max = 2.75V
R_fixture = 1000Ohm
C_fixture = 0F
|   Time   V(typ)   V(min)   V(max)
0s        13.26mV    20.18mV    9.463mV
783.1ps   -15.37mV   18.88mV    -168.1mV
1.156ns   -104.6mV   -5.981mV   57.37mV
1.812ns   214.3mV    -12.65mV   443.1mV
3.578ns   892.4mV    616.9mV    1.155V
7.707ns   1.758V     1.446V     2.059V
11.85ns   2.155V     1.85V      2.452V
19.12ns   2.411V     2.131V     2.687V
41.86ns   2.499V     2.251V     2.748V
199.9ns   2.5V       2.25V      2.75V
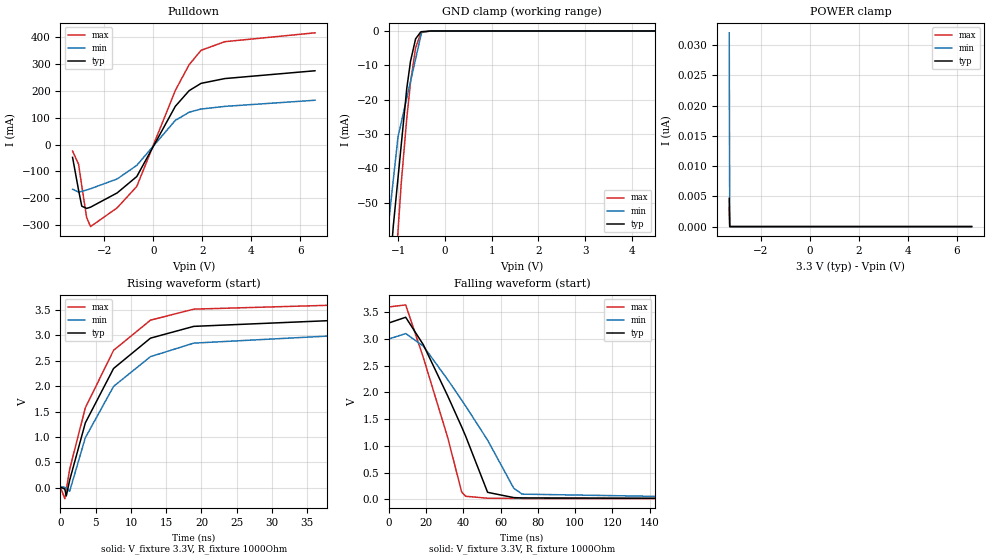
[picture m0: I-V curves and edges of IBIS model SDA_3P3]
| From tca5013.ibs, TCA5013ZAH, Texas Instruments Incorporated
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[Model]   SDA_3P3
Model_type   I/O_open_drain
Polarity   Non-Inverting
Enable   Active-Low
Vinl = .4
Vinh = 1.4
Vmeas = 1.65
Vref = 3.3
Cref = 15pF
Rref = 1000
|   typ   min   max
C_comp   2.166p   1.754p   2.419p
|C_comp (Low state)   2.166p   1.754p   2.419p
|C_comp (High state)   2.217p   1.811p   2.443p
[Voltage Range]   3.3   3   3.6
[Temperature Range]   27   125   -40
[Pullup Reference]   3.3   3   3.6
[Pulldown Reference]   0   0   0
[Power Clamp Reference]   3.3   3   3.6
[GND Clamp Reference]   0   0   0
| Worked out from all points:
|   slope of the pulldown table from 0 to 0.495 V, typ, clamps not added: 5.81 ohm
|   GND clamp passes 1 mA (typ) near -0.58 V on its own axis
|   falling waveform, V_fixture 3.3V, R_fixture 1000Ohm: 20-80 % time 25.1ns typ, 32.8ns min, 18.5ns max; typ from 3.3 V to 0.014 V
|   rising waveform, V_fixture 3.3V, R_fixture 1000Ohm: 20-80 % time 7.44ns typ, 8.08ns min, 6.8ns max; typ from 0.014 V to 3.3 V
[Pulldown]
|   Voltage   I(typ)   I(min)   I(max)
-3.3V     -47.51mA   -165.8mA   -24.02mA
-3.053V   -170.2mA   -176.6mA   -73.55mA
-2.924V   -228.7mA   -174.1mA   -153.5mA
-2.726V   -237.1mA   -168.5mA   -270.5mA
-2.567V   -232.5mA   -164mA     -304.6mA
-1.478V   -179.5mA   -127.7mA   -235mA
-676.5mV  -118.6mA   -77.16mA   -155.3mA
897.6mV   142.2mA    89.87mA    201.3mA
1.462V    200.3mA    120.1mA    296.7mA
1.947V    227.3mA    132mA      350mA
2.917V    245.1mA    141.8mA    382.1mA
6.6V      274.1mA    164.6mA    415mA
[GND Clamp]
|   Voltage   I(typ)   I(min)   I(max)
-3.3V     -720mA     -397.6mA   -1.003A
-1.369V   -102.5mA   -76.57mA   -132.2mA
-1.102V   -56.64mA   -43.23mA   -78.35mA
-1.003V   -42.87mA   -30.89mA   -58.4mA
-933mV    -33.11mA   -26.65mA   -44.26mA
-815.1mV  -16.71mA   -19.52mA   -25.43mA
-735.9mV  -8.857mA   -14.74mA   -15.09mA
-627mV    -2.285mA   -8.157mA   -4.932mA
-518.1mV  -280.7uA   -1.576mA   -662.5uA
-498.1mV  -187.3uA   -366.1uA   -429.2uA
-310.2mV  -1.116uA   -7.615uA   -796.5nA
6.6V      0A         0A         0A
[POWER Clamp]
|   Voltage   I(typ)   I(min)   I(max)
-3.3V     4.664nA    32.04nA    3.166nA
-3.28V    0A         0A         0A
-3.27V    0A         0A         0A
6.6V      0A         0A         0A
[Ramp]
R_load = 1000
|   typ   min   max
dV/dt_r   1.9714/7.36609e-09   1.78759/8.00521e-09   2.15356/6.77914e-09
dV/dt_f   1.97133/2.50764e-08   1.78729/3.28016e-08   2.15354/1.84955e-08
[Falling Waveform]
V_fixture = 3.3V
V_fixture_min = 3V
V_fixture_max = 3.6V
R_fixture = 1000Ohm
C_fixture = 0F
|   Time   V(typ)   V(min)   V(max)
0s        3.3V       3V         3.6V
9.077ns   3.407V     3.102V     3.638V
18.56ns   2.891V     2.866V     2.649V
31.55ns   1.939V     2.242V     1.163V
39.11ns   1.354V     1.856V     135.2mV
41.24ns   1.181V     1.745V     55.95mV
53.01ns   130mV      1.107V     19.98mV
67.04ns   31.05mV    206.2mV    15.11mV
71.52ns   25.3mV     96.28mV    14.96mV
199.9ns   14.45mV    21.18mV    10.77mV
[Rising Waveform]
V_fixture = 3.3V
V_fixture_min = 3V
V_fixture_max = 3.6V
R_fixture = 1000Ohm
C_fixture = 0F
|   Time   V(typ)   V(min)   V(max)
0s        14.33mV    20.67mV    10.74mV
618.2ps   -24.63mV   10.95mV    -214.5mV
829.1ps   -161.4mV   -11.38mV   -40.71mV
1.303ns   147.7mV    -68.48mV   364.6mV
3.529ns   1.278V     985.6mV    1.574V
7.534ns   2.349V     1.996V     2.706V
12.77ns   2.946V     2.582V     3.3V
18.91ns   3.178V     2.848V     3.517V
39.36ns   3.298V     2.997V     3.598V
199.9ns   3.3V       3V         3.6V
